VERSION 5.8 ;
BUSBITCHARS "[]" ;

UNITS
  DATABASE MICRONS 1000 ;
END UNITS

PROPERTYDEFINITIONS
  MACRO expanded_util REAL ;
END PROPERTYDEFINITIONS

LAYER OVERLAP
  TYPE OVERLAP ;
END OVERLAP

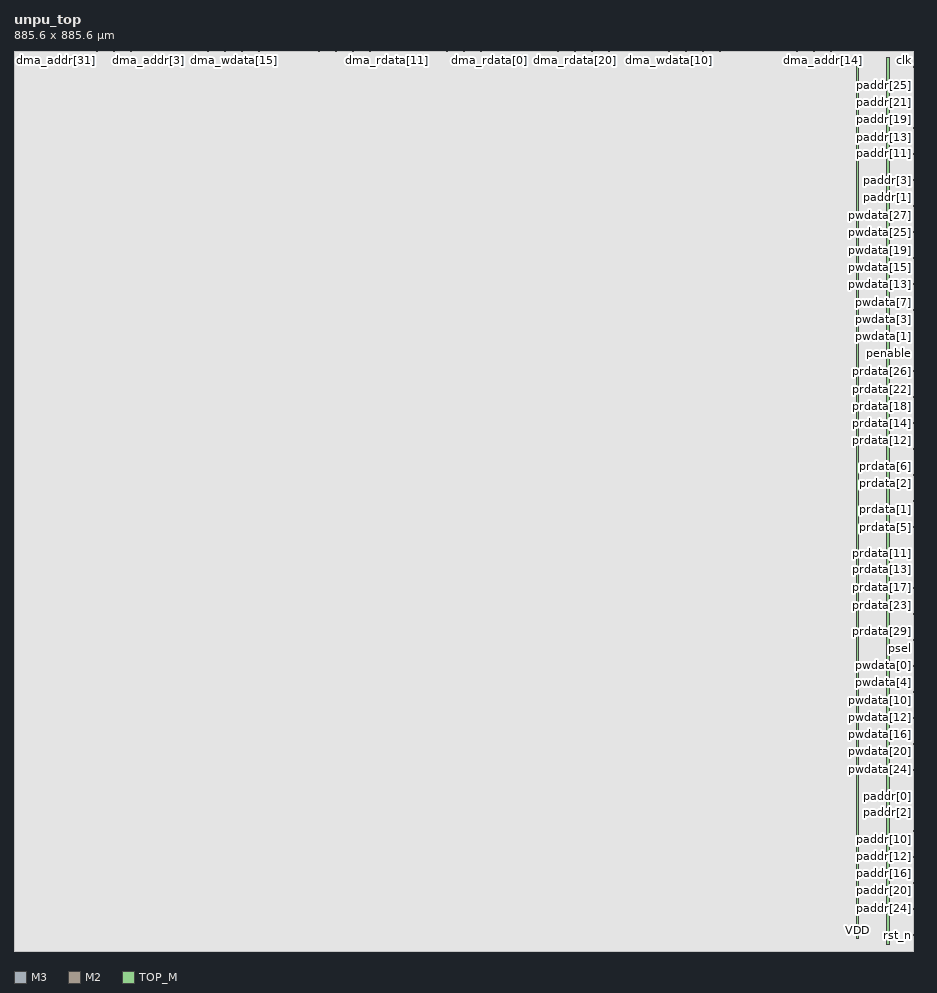
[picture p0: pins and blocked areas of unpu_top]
MACRO unpu_top
  CLASS BLOCK ;
  ORIGIN 0 0 ;
  SIZE 885.6 BY 885.6 ;
  SYMMETRY X Y ;
  PIN clk
    DIRECTION INPUT ;
    USE CLOCK ;
    PORT
      LAYER M3 ;
        RECT 884.875 878.13 885.6 878.41 ;
    END
  END clk
  PIN rst_n
    DIRECTION INPUT ;
    USE SIGNAL ;
    PORT
      LAYER M3 ;
        RECT 884.875 15.59 885.6 15.87 ;
    END
  END rst_n
  PIN paddr[31]
    DIRECTION INPUT ;
    USE SIGNAL ;
    PORT
      LAYER M3 ;
        RECT 884.875 869.59 885.6 869.87 ;
    END
  END paddr[31]
  PIN paddr[30]
    DIRECTION INPUT ;
    USE SIGNAL ;
    PORT
      LAYER M3 ;
        RECT 884.875 24.13 885.6 24.41 ;
    END
  END paddr[30]
  PIN paddr[29]
    DIRECTION INPUT ;
    USE SIGNAL ;
    PORT
      LAYER M3 ;
        RECT 884.875 861.05 885.6 861.33 ;
    END
  END paddr[29]
  PIN paddr[28]
    DIRECTION INPUT ;
    USE SIGNAL ;
    PORT
      LAYER M3 ;
        RECT 884.875 32.67 885.6 32.95 ;
    END
  END paddr[28]
  PIN paddr[27]
    DIRECTION INPUT ;
    USE SIGNAL ;
    PORT
      LAYER M3 ;
        RECT 884.875 852.51 885.6 852.79 ;
    END
  END paddr[27]
  PIN paddr[26]
    DIRECTION INPUT ;
    USE SIGNAL ;
    PORT
      LAYER M3 ;
        RECT 884.875 41.21 885.6 41.49 ;
    END
  END paddr[26]
  PIN paddr[25]
    DIRECTION INPUT ;
    USE SIGNAL ;
    PORT
      LAYER M3 ;
        RECT 884.875 843.97 885.6 844.25 ;
    END
  END paddr[25]
  PIN paddr[24]
    DIRECTION INPUT ;
    USE SIGNAL ;
    PORT
      LAYER M3 ;
        RECT 884.875 49.75 885.6 50.03 ;
    END
  END paddr[24]
  PIN paddr[23]
    DIRECTION INPUT ;
    USE SIGNAL ;
    PORT
      LAYER M3 ;
        RECT 884.875 835.43 885.6 835.71 ;
    END
  END paddr[23]
  PIN paddr[22]
    DIRECTION INPUT ;
    USE SIGNAL ;
    PORT
      LAYER M3 ;
        RECT 884.875 58.29 885.6 58.57 ;
    END
  END paddr[22]
  PIN paddr[21]
    DIRECTION INPUT ;
    USE SIGNAL ;
    PORT
      LAYER M3 ;
        RECT 884.875 826.89 885.6 827.17 ;
    END
  END paddr[21]
  PIN paddr[20]
    DIRECTION INPUT ;
    USE SIGNAL ;
    PORT
      LAYER M3 ;
        RECT 884.875 66.83 885.6 67.11 ;
    END
  END paddr[20]
  PIN paddr[19]
    DIRECTION INPUT ;
    USE SIGNAL ;
    PORT
      LAYER M3 ;
        RECT 884.875 818.35 885.6 818.63 ;
    END
  END paddr[19]
  PIN paddr[18]
    DIRECTION INPUT ;
    USE SIGNAL ;
    PORT
      LAYER M3 ;
        RECT 884.875 75.37 885.6 75.65 ;
    END
  END paddr[18]
  PIN paddr[17]
    DIRECTION INPUT ;
    USE SIGNAL ;
    PORT
      LAYER M3 ;
        RECT 884.875 809.81 885.6 810.09 ;
    END
  END paddr[17]
  PIN paddr[16]
    DIRECTION INPUT ;
    USE SIGNAL ;
    PORT
      LAYER M3 ;
        RECT 884.875 83.91 885.6 84.19 ;
    END
  END paddr[16]
  PIN paddr[15]
    DIRECTION INPUT ;
    USE SIGNAL ;
    PORT
      LAYER M3 ;
        RECT 884.875 801.27 885.6 801.55 ;
    END
  END paddr[15]
  PIN paddr[14]
    DIRECTION INPUT ;
    USE SIGNAL ;
    PORT
      LAYER M3 ;
        RECT 884.875 92.45 885.6 92.73 ;
    END
  END paddr[14]
  PIN paddr[13]
    DIRECTION INPUT ;
    USE SIGNAL ;
    PORT
      LAYER M3 ;
        RECT 884.875 792.73 885.6 793.01 ;
    END
  END paddr[13]
  PIN paddr[12]
    DIRECTION INPUT ;
    USE SIGNAL ;
    PORT
      LAYER M3 ;
        RECT 884.875 100.99 885.6 101.27 ;
    END
  END paddr[12]
  PIN paddr[11]
    DIRECTION INPUT ;
    USE SIGNAL ;
    PORT
      LAYER M3 ;
        RECT 884.875 784.19 885.6 784.47 ;
    END
  END paddr[11]
  PIN paddr[10]
    DIRECTION INPUT ;
    USE SIGNAL ;
    PORT
      LAYER M3 ;
        RECT 884.875 109.53 885.6 109.81 ;
    END
  END paddr[10]
  PIN paddr[9]
    DIRECTION INPUT ;
    USE SIGNAL ;
    PORT
      LAYER M3 ;
        RECT 884.875 775.65 885.6 775.93 ;
    END
  END paddr[9]
  PIN paddr[8]
    DIRECTION INPUT ;
    USE SIGNAL ;
    PORT
      LAYER M3 ;
        RECT 884.875 118.07 885.6 118.35 ;
    END
  END paddr[8]
  PIN paddr[7]
    DIRECTION INPUT ;
    USE SIGNAL ;
    PORT
      LAYER M3 ;
        RECT 884.875 767.11 885.6 767.39 ;
    END
  END paddr[7]
  PIN paddr[6]
    DIRECTION INPUT ;
    USE SIGNAL ;
    PORT
      LAYER M3 ;
        RECT 884.875 126.61 885.6 126.89 ;
    END
  END paddr[6]
  PIN paddr[5]
    DIRECTION INPUT ;
    USE SIGNAL ;
    PORT
      LAYER M3 ;
        RECT 884.875 758.57 885.6 758.85 ;
    END
  END paddr[5]
  PIN paddr[4]
    DIRECTION INPUT ;
    USE SIGNAL ;
    PORT
      LAYER M3 ;
        RECT 884.875 135.15 885.6 135.43 ;
    END
  END paddr[4]
  PIN paddr[3]
    DIRECTION INPUT ;
    USE SIGNAL ;
    PORT
      LAYER M3 ;
        RECT 884.875 750.03 885.6 750.31 ;
    END
  END paddr[3]
  PIN paddr[2]
    DIRECTION INPUT ;
    USE SIGNAL ;
    PORT
      LAYER M3 ;
        RECT 884.875 143.69 885.6 143.97 ;
    END
  END paddr[2]
  PIN paddr[1]
    DIRECTION INPUT ;
    USE SIGNAL ;
    PORT
      LAYER M3 ;
        RECT 884.875 741.49 885.6 741.77 ;
    END
  END paddr[1]
  PIN paddr[0]
    DIRECTION INPUT ;
    USE SIGNAL ;
    PORT
      LAYER M3 ;
        RECT 884.875 152.23 885.6 152.51 ;
    END
  END paddr[0]
  PIN pwdata[31]
    DIRECTION INPUT ;
    USE SIGNAL ;
    PORT
      LAYER M3 ;
        RECT 884.875 732.95 885.6 733.23 ;
    END
  END pwdata[31]
  PIN pwdata[30]
    DIRECTION INPUT ;
    USE SIGNAL ;
    PORT
      LAYER M3 ;
        RECT 884.875 160.77 885.6 161.05 ;
    END
  END pwdata[30]
  PIN pwdata[29]
    DIRECTION INPUT ;
    USE SIGNAL ;
    PORT
      LAYER M3 ;
        RECT 884.875 724.41 885.6 724.69 ;
    END
  END pwdata[29]
  PIN pwdata[28]
    DIRECTION INPUT ;
    USE SIGNAL ;
    PORT
      LAYER M3 ;
        RECT 884.875 169.31 885.6 169.59 ;
    END
  END pwdata[28]
  PIN pwdata[27]
    DIRECTION INPUT ;
    USE SIGNAL ;
    PORT
      LAYER M3 ;
        RECT 884.875 715.87 885.6 716.15 ;
    END
  END pwdata[27]
  PIN pwdata[26]
    DIRECTION INPUT ;
    USE SIGNAL ;
    PORT
      LAYER M3 ;
        RECT 884.875 177.85 885.6 178.13 ;
    END
  END pwdata[26]
  PIN pwdata[25]
    DIRECTION INPUT ;
    USE SIGNAL ;
    PORT
      LAYER M3 ;
        RECT 884.875 707.33 885.6 707.61 ;
    END
  END pwdata[25]
  PIN pwdata[24]
    DIRECTION INPUT ;
    USE SIGNAL ;
    PORT
      LAYER M3 ;
        RECT 884.875 186.39 885.6 186.67 ;
    END
  END pwdata[24]
  PIN pwdata[23]
    DIRECTION INPUT ;
    USE SIGNAL ;
    PORT
      LAYER M3 ;
        RECT 884.875 698.79 885.6 699.07 ;
    END
  END pwdata[23]
  PIN pwdata[22]
    DIRECTION INPUT ;
    USE SIGNAL ;
    PORT
      LAYER M3 ;
        RECT 884.875 194.93 885.6 195.21 ;
    END
  END pwdata[22]
  PIN pwdata[21]
    DIRECTION INPUT ;
    USE SIGNAL ;
    PORT
      LAYER M3 ;
        RECT 884.875 690.25 885.6 690.53 ;
    END
  END pwdata[21]
  PIN pwdata[20]
    DIRECTION INPUT ;
    USE SIGNAL ;
    PORT
      LAYER M3 ;
        RECT 884.875 203.47 885.6 203.75 ;
    END
  END pwdata[20]
  PIN pwdata[19]
    DIRECTION INPUT ;
    USE SIGNAL ;
    PORT
      LAYER M3 ;
        RECT 884.875 681.71 885.6 681.99 ;
    END
  END pwdata[19]
  PIN pwdata[18]
    DIRECTION INPUT ;
    USE SIGNAL ;
    PORT
      LAYER M3 ;
        RECT 884.875 212.01 885.6 212.29 ;
    END
  END pwdata[18]
  PIN pwdata[17]
    DIRECTION INPUT ;
    USE SIGNAL ;
    PORT
      LAYER M3 ;
        RECT 884.875 673.17 885.6 673.45 ;
    END
  END pwdata[17]
  PIN pwdata[16]
    DIRECTION INPUT ;
    USE SIGNAL ;
    PORT
      LAYER M3 ;
        RECT 884.875 220.55 885.6 220.83 ;
    END
  END pwdata[16]
  PIN pwdata[15]
    DIRECTION INPUT ;
    USE SIGNAL ;
    PORT
      LAYER M3 ;
        RECT 884.875 664.63 885.6 664.91 ;
    END
  END pwdata[15]
  PIN pwdata[14]
    DIRECTION INPUT ;
    USE SIGNAL ;
    PORT
      LAYER M3 ;
        RECT 884.875 229.09 885.6 229.37 ;
    END
  END pwdata[14]
  PIN pwdata[13]
    DIRECTION INPUT ;
    USE SIGNAL ;
    PORT
      LAYER M3 ;
        RECT 884.875 656.09 885.6 656.37 ;
    END
  END pwdata[13]
  PIN pwdata[12]
    DIRECTION INPUT ;
    USE SIGNAL ;
    PORT
      LAYER M3 ;
        RECT 884.875 237.63 885.6 237.91 ;
    END
  END pwdata[12]
  PIN pwdata[11]
    DIRECTION INPUT ;
    USE SIGNAL ;
    PORT
      LAYER M3 ;
        RECT 884.875 647.55 885.6 647.83 ;
    END
  END pwdata[11]
  PIN pwdata[10]
    DIRECTION INPUT ;
    USE SIGNAL ;
    PORT
      LAYER M3 ;
        RECT 884.875 246.17 885.6 246.45 ;
    END
  END pwdata[10]
  PIN pwdata[9]
    DIRECTION INPUT ;
    USE SIGNAL ;
    PORT
      LAYER M3 ;
        RECT 884.875 639.01 885.6 639.29 ;
    END
  END pwdata[9]
  PIN pwdata[8]
    DIRECTION INPUT ;
    USE SIGNAL ;
    PORT
      LAYER M3 ;
        RECT 884.875 254.71 885.6 254.99 ;
    END
  END pwdata[8]
  PIN pwdata[7]
    DIRECTION INPUT ;
    USE SIGNAL ;
    PORT
      LAYER M3 ;
        RECT 884.875 630.47 885.6 630.75 ;
    END
  END pwdata[7]
  PIN pwdata[6]
    DIRECTION INPUT ;
    USE SIGNAL ;
    PORT
      LAYER M3 ;
        RECT 884.875 263.25 885.6 263.53 ;
    END
  END pwdata[6]
  PIN pwdata[5]
    DIRECTION INPUT ;
    USE SIGNAL ;
    PORT
      LAYER M3 ;
        RECT 884.875 621.93 885.6 622.21 ;
    END
  END pwdata[5]
  PIN pwdata[4]
    DIRECTION INPUT ;
    USE SIGNAL ;
    PORT
      LAYER M3 ;
        RECT 884.875 271.79 885.6 272.07 ;
    END
  END pwdata[4]
  PIN pwdata[3]
    DIRECTION INPUT ;
    USE SIGNAL ;
    PORT
      LAYER M3 ;
        RECT 884.875 613.39 885.6 613.67 ;
    END
  END pwdata[3]
  PIN pwdata[2]
    DIRECTION INPUT ;
    USE SIGNAL ;
    PORT
      LAYER M3 ;
        RECT 884.875 280.33 885.6 280.61 ;
    END
  END pwdata[2]
  PIN pwdata[1]
    DIRECTION INPUT ;
    USE SIGNAL ;
    PORT
      LAYER M3 ;
        RECT 884.875 604.85 885.6 605.13 ;
    END
  END pwdata[1]
  PIN pwdata[0]
    DIRECTION INPUT ;
    USE SIGNAL ;
    PORT
      LAYER M3 ;
        RECT 884.875 288.87 885.6 289.15 ;
    END
  END pwdata[0]
  PIN pwrite
    DIRECTION INPUT ;
    USE SIGNAL ;
    PORT
      LAYER M3 ;
        RECT 884.875 596.31 885.6 596.59 ;
    END
  END pwrite
  PIN psel
    DIRECTION INPUT ;
    USE SIGNAL ;
    PORT
      LAYER M3 ;
        RECT 884.875 297.41 885.6 297.69 ;
    END
  END psel
  PIN penable
    DIRECTION INPUT ;
    USE SIGNAL ;
    PORT
      LAYER M3 ;
        RECT 884.875 587.77 885.6 588.05 ;
    END
  END penable
  PIN prdata[31]
    DIRECTION OUTPUT ;
    USE SIGNAL ;
    PORT
      LAYER M3 ;
        RECT 884.875 305.95 885.6 306.23 ;
    END
  END prdata[31]
  PIN prdata[30]
    DIRECTION OUTPUT ;
    USE SIGNAL ;
    PORT
      LAYER M3 ;
        RECT 884.875 579.23 885.6 579.51 ;
    END
  END prdata[30]
  PIN prdata[29]
    DIRECTION OUTPUT ;
    USE SIGNAL ;
    PORT
      LAYER M3 ;
        RECT 884.875 314.49 885.6 314.77 ;
    END
  END prdata[29]
  PIN prdata[28]
    DIRECTION OUTPUT ;
    USE SIGNAL ;
    PORT
      LAYER M3 ;
        RECT 884.875 570.69 885.6 570.97 ;
    END
  END prdata[28]
  PIN prdata[27]
    DIRECTION OUTPUT ;
    USE SIGNAL ;
    PORT
      LAYER M3 ;
        RECT 884.875 323.03 885.6 323.31 ;
    END
  END prdata[27]
  PIN prdata[26]
    DIRECTION OUTPUT ;
    USE SIGNAL ;
    PORT
      LAYER M3 ;
        RECT 884.875 562.15 885.6 562.43 ;
    END
  END prdata[26]
  PIN prdata[25]
    DIRECTION OUTPUT ;
    USE SIGNAL ;
    PORT
      LAYER M3 ;
        RECT 884.875 331.57 885.6 331.85 ;
    END
  END prdata[25]
  PIN prdata[24]
    DIRECTION OUTPUT ;
    USE SIGNAL ;
    PORT
      LAYER M3 ;
        RECT 884.875 553.61 885.6 553.89 ;
    END
  END prdata[24]
  PIN prdata[23]
    DIRECTION OUTPUT ;
    USE SIGNAL ;
    PORT
      LAYER M3 ;
        RECT 884.875 340.11 885.6 340.39 ;
    END
  END prdata[23]
  PIN prdata[22]
    DIRECTION OUTPUT ;
    USE SIGNAL ;
    PORT
      LAYER M3 ;
        RECT 884.875 545.07 885.6 545.35 ;
    END
  END prdata[22]
  PIN prdata[21]
    DIRECTION OUTPUT ;
    USE SIGNAL ;
    PORT
      LAYER M3 ;
        RECT 884.875 348.65 885.6 348.93 ;
    END
  END prdata[21]
  PIN prdata[20]
    DIRECTION OUTPUT ;
    USE SIGNAL ;
    PORT
      LAYER M3 ;
        RECT 884.875 536.53 885.6 536.81 ;
    END
  END prdata[20]
  PIN prdata[19]
    DIRECTION OUTPUT ;
    USE SIGNAL ;
    PORT
      LAYER M3 ;
        RECT 884.875 357.19 885.6 357.47 ;
    END
  END prdata[19]
  PIN prdata[18]
    DIRECTION OUTPUT ;
    USE SIGNAL ;
    PORT
      LAYER M3 ;
        RECT 884.875 527.99 885.6 528.27 ;
    END
  END prdata[18]
  PIN prdata[17]
    DIRECTION OUTPUT ;
    USE SIGNAL ;
    PORT
      LAYER M3 ;
        RECT 884.875 365.73 885.6 366.01 ;
    END
  END prdata[17]
  PIN prdata[16]
    DIRECTION OUTPUT ;
    USE SIGNAL ;
    PORT
      LAYER M3 ;
        RECT 884.875 519.45 885.6 519.73 ;
    END
  END prdata[16]
  PIN prdata[15]
    DIRECTION OUTPUT ;
    USE SIGNAL ;
    PORT
      LAYER M3 ;
        RECT 884.875 374.27 885.6 374.55 ;
    END
  END prdata[15]
  PIN prdata[14]
    DIRECTION OUTPUT ;
    USE SIGNAL ;
    PORT
      LAYER M3 ;
        RECT 884.875 510.91 885.6 511.19 ;
    END
  END prdata[14]
  PIN prdata[13]
    DIRECTION OUTPUT ;
    USE SIGNAL ;
    PORT
      LAYER M3 ;
        RECT 884.875 382.81 885.6 383.09 ;
    END
  END prdata[13]
  PIN prdata[12]
    DIRECTION OUTPUT ;
    USE SIGNAL ;
    PORT
      LAYER M3 ;
        RECT 884.875 502.37 885.6 502.65 ;
    END
  END prdata[12]
  PIN prdata[11]
    DIRECTION OUTPUT ;
    USE SIGNAL ;
    PORT
      LAYER M3 ;
        RECT 884.875 391.35 885.6 391.63 ;
    END
  END prdata[11]
  PIN prdata[10]
    DIRECTION OUTPUT ;
    USE SIGNAL ;
    PORT
      LAYER M3 ;
        RECT 884.875 493.83 885.6 494.11 ;
    END
  END prdata[10]
  PIN prdata[9]
    DIRECTION OUTPUT ;
    USE SIGNAL ;
    PORT
      LAYER M3 ;
        RECT 884.875 399.89 885.6 400.17 ;
    END
  END prdata[9]
  PIN prdata[8]
    DIRECTION OUTPUT ;
    USE SIGNAL ;
    PORT
      LAYER M3 ;
        RECT 884.875 485.29 885.6 485.57 ;
    END
  END prdata[8]
  PIN prdata[7]
    DIRECTION OUTPUT ;
    USE SIGNAL ;
    PORT
      LAYER M3 ;
        RECT 884.875 408.43 885.6 408.71 ;
    END
  END prdata[7]
  PIN prdata[6]
    DIRECTION OUTPUT ;
    USE SIGNAL ;
    PORT
      LAYER M3 ;
        RECT 884.875 476.75 885.6 477.03 ;
    END
  END prdata[6]
  PIN prdata[5]
    DIRECTION OUTPUT ;
    USE SIGNAL ;
    PORT
      LAYER M3 ;
        RECT 884.875 416.97 885.6 417.25 ;
    END
  END prdata[5]
  PIN prdata[4]
    DIRECTION OUTPUT ;
    USE SIGNAL ;
    PORT
      LAYER M3 ;
        RECT 884.875 468.21 885.6 468.49 ;
    END
  END prdata[4]
  PIN prdata[3]
    DIRECTION OUTPUT ;
    USE SIGNAL ;
    PORT
      LAYER M3 ;
        RECT 884.875 425.51 885.6 425.79 ;
    END
  END prdata[3]
  PIN prdata[2]
    DIRECTION OUTPUT ;
    USE SIGNAL ;
    PORT
      LAYER M3 ;
        RECT 884.875 459.67 885.6 459.95 ;
    END
  END prdata[2]
  PIN prdata[1]
    DIRECTION OUTPUT ;
    USE SIGNAL ;
    PORT
      LAYER M3 ;
        RECT 884.875 434.05 885.6 434.33 ;
    END
  END prdata[1]
  PIN prdata[0]
    DIRECTION OUTPUT ;
    USE SIGNAL ;
    PORT
      LAYER M3 ;
        RECT 884.875 451.13 885.6 451.41 ;
    END
  END prdata[0]
  PIN pready
    DIRECTION OUTPUT ;
    USE SIGNAL ;
    PORT
      LAYER M3 ;
        RECT 884.875 442.59 885.6 442.87 ;
    END
  END pready
  PIN dma_addr[31]
    DIRECTION OUTPUT ;
    USE SIGNAL ;
    PORT
      LAYER M2 ;
        RECT 14.26 884.875 14.54 885.6 ;
    END
  END dma_addr[31]
  PIN dma_addr[30]
    DIRECTION OUTPUT ;
    USE SIGNAL ;
    PORT
      LAYER M2 ;
        RECT 862.66 884.875 862.94 885.6 ;
    END
  END dma_addr[30]
  PIN dma_addr[29]
    DIRECTION OUTPUT ;
    USE SIGNAL ;
    PORT
      LAYER M2 ;
        RECT 22.66 884.875 22.94 885.6 ;
    END
  END dma_addr[29]
  PIN dma_addr[28]
    DIRECTION OUTPUT ;
    USE SIGNAL ;
    PORT
      LAYER M2 ;
        RECT 854.26 884.875 854.54 885.6 ;
    END
  END dma_addr[28]
  PIN dma_addr[27]
    DIRECTION OUTPUT ;
    USE SIGNAL ;
    PORT
      LAYER M2 ;
        RECT 31.06 884.875 31.34 885.6 ;
    END
  END dma_addr[27]
  PIN dma_addr[26]
    DIRECTION OUTPUT ;
    USE SIGNAL ;
    PORT
      LAYER M2 ;
        RECT 845.86 884.875 846.14 885.6 ;
    END
  END dma_addr[26]
  PIN dma_addr[25]
    DIRECTION OUTPUT ;
    USE SIGNAL ;
    PORT
      LAYER M2 ;
        RECT 39.46 884.875 39.74 885.6 ;
    END
  END dma_addr[25]
  PIN dma_addr[24]
    DIRECTION OUTPUT ;
    USE SIGNAL ;
    PORT
      LAYER M2 ;
        RECT 837.46 884.875 837.74 885.6 ;
    END
  END dma_addr[24]
  PIN dma_addr[23]
    DIRECTION OUTPUT ;
    USE SIGNAL ;
    PORT
      LAYER M2 ;
        RECT 47.86 884.875 48.14 885.6 ;
    END
  END dma_addr[23]
  PIN dma_addr[22]
    DIRECTION OUTPUT ;
    USE SIGNAL ;
    PORT
      LAYER M2 ;
        RECT 829.06 884.875 829.34 885.6 ;
    END
  END dma_addr[22]
  PIN dma_addr[21]
    DIRECTION OUTPUT ;
    USE SIGNAL ;
    PORT
      LAYER M2 ;
        RECT 56.26 884.875 56.54 885.6 ;
    END
  END dma_addr[21]
  PIN dma_addr[20]
    DIRECTION OUTPUT ;
    USE SIGNAL ;
    PORT
      LAYER M2 ;
        RECT 820.66 884.875 820.94 885.6 ;
    END
  END dma_addr[20]
  PIN dma_addr[19]
    DIRECTION OUTPUT ;
    USE SIGNAL ;
    PORT
      LAYER M2 ;
        RECT 64.66 884.875 64.94 885.6 ;
    END
  END dma_addr[19]
  PIN dma_addr[18]
    DIRECTION OUTPUT ;
    USE SIGNAL ;
    PORT
      LAYER M2 ;
        RECT 812.26 884.875 812.54 885.6 ;
    END
  END dma_addr[18]
  PIN dma_addr[17]
    DIRECTION OUTPUT ;
    USE SIGNAL ;
    PORT
      LAYER M2 ;
        RECT 73.06 884.875 73.34 885.6 ;
    END
  END dma_addr[17]
  PIN dma_addr[16]
    DIRECTION OUTPUT ;
    USE SIGNAL ;
    PORT
      LAYER M2 ;
        RECT 803.86 884.875 804.14 885.6 ;
    END
  END dma_addr[16]
  PIN dma_addr[15]
    DIRECTION OUTPUT ;
    USE SIGNAL ;
    PORT
      LAYER M2 ;
        RECT 81.46 884.875 81.74 885.6 ;
    END
  END dma_addr[15]
  PIN dma_addr[14]
    DIRECTION OUTPUT ;
    USE SIGNAL ;
    PORT
      LAYER M2 ;
        RECT 795.46 884.875 795.74 885.6 ;
    END
  END dma_addr[14]
  PIN dma_addr[13]
    DIRECTION OUTPUT ;
    USE SIGNAL ;
    PORT
      LAYER M2 ;
        RECT 89.86 884.875 90.14 885.6 ;
    END
  END dma_addr[13]
  PIN dma_addr[12]
    DIRECTION OUTPUT ;
    USE SIGNAL ;
    PORT
      LAYER M2 ;
        RECT 787.06 884.875 787.34 885.6 ;
    END
  END dma_addr[12]
  PIN dma_addr[11]
    DIRECTION OUTPUT ;
    USE SIGNAL ;
    PORT
      LAYER M2 ;
        RECT 98.26 884.875 98.54 885.6 ;
    END
  END dma_addr[11]
  PIN dma_addr[10]
    DIRECTION OUTPUT ;
    USE SIGNAL ;
    PORT
      LAYER M2 ;
        RECT 778.66 884.875 778.94 885.6 ;
    END
  END dma_addr[10]
  PIN dma_addr[9]
    DIRECTION OUTPUT ;
    USE SIGNAL ;
    PORT
      LAYER M2 ;
        RECT 106.66 884.875 106.94 885.6 ;
    END
  END dma_addr[9]
  PIN dma_addr[8]
    DIRECTION OUTPUT ;
    USE SIGNAL ;
    PORT
      LAYER M2 ;
        RECT 770.26 884.875 770.54 885.6 ;
    END
  END dma_addr[8]
  PIN dma_addr[7]
    DIRECTION OUTPUT ;
    USE SIGNAL ;
    PORT
      LAYER M2 ;
        RECT 115.06 884.875 115.34 885.6 ;
    END
  END dma_addr[7]
  PIN dma_addr[6]
    DIRECTION OUTPUT ;
    USE SIGNAL ;
    PORT
      LAYER M2 ;
        RECT 761.86 884.875 762.14 885.6 ;
    END
  END dma_addr[6]
  PIN dma_addr[5]
    DIRECTION OUTPUT ;
    USE SIGNAL ;
    PORT
      LAYER M2 ;
        RECT 123.46 884.875 123.74 885.6 ;
    END
  END dma_addr[5]
  PIN dma_addr[4]
    DIRECTION OUTPUT ;
    USE SIGNAL ;
    PORT
      LAYER M2 ;
        RECT 753.46 884.875 753.74 885.6 ;
    END
  END dma_addr[4]
  PIN dma_addr[3]
    DIRECTION OUTPUT ;
    USE SIGNAL ;
    PORT
      LAYER M2 ;
        RECT 131.86 884.875 132.14 885.6 ;
    END
  END dma_addr[3]
  PIN dma_addr[2]
    DIRECTION OUTPUT ;
    USE SIGNAL ;
    PORT
      LAYER M2 ;
        RECT 745.06 884.875 745.34 885.6 ;
    END
  END dma_addr[2]
  PIN dma_addr[1]
    DIRECTION OUTPUT ;
    USE SIGNAL ;
    PORT
      LAYER M2 ;
        RECT 140.26 884.875 140.54 885.6 ;
    END
  END dma_addr[1]
  PIN dma_addr[0]
    DIRECTION OUTPUT ;
    USE SIGNAL ;
    PORT
      LAYER M2 ;
        RECT 736.66 884.875 736.94 885.6 ;
    END
  END dma_addr[0]
  PIN dma_wdata[31]
    DIRECTION OUTPUT ;
    USE SIGNAL ;
    PORT
      LAYER M2 ;
        RECT 148.66 884.875 148.94 885.6 ;
    END
  END dma_wdata[31]
  PIN dma_wdata[30]
    DIRECTION OUTPUT ;
    USE SIGNAL ;
    PORT
      LAYER M2 ;
        RECT 728.26 884.875 728.54 885.6 ;
    END
  END dma_wdata[30]
  PIN dma_wdata[29]
    DIRECTION OUTPUT ;
    USE SIGNAL ;
    PORT
      LAYER M2 ;
        RECT 157.06 884.875 157.34 885.6 ;
    END
  END dma_wdata[29]
  PIN dma_wdata[28]
    DIRECTION OUTPUT ;
    USE SIGNAL ;
    PORT
      LAYER M2 ;
        RECT 719.86 884.875 720.14 885.6 ;
    END
  END dma_wdata[28]
  PIN dma_wdata[27]
    DIRECTION OUTPUT ;
    USE SIGNAL ;
    PORT
      LAYER M2 ;
        RECT 165.46 884.875 165.74 885.6 ;
    END
  END dma_wdata[27]
  PIN dma_wdata[26]
    DIRECTION OUTPUT ;
    USE SIGNAL ;
    PORT
      LAYER M2 ;
        RECT 711.46 884.875 711.74 885.6 ;
    END
  END dma_wdata[26]
  PIN dma_wdata[25]
    DIRECTION OUTPUT ;
    USE SIGNAL ;
    PORT
      LAYER M2 ;
        RECT 173.86 884.875 174.14 885.6 ;
    END
  END dma_wdata[25]
  PIN dma_wdata[24]
    DIRECTION OUTPUT ;
    USE SIGNAL ;
    PORT
      LAYER M2 ;
        RECT 703.06 884.875 703.34 885.6 ;
    END
  END dma_wdata[24]
  PIN dma_wdata[23]
    DIRECTION OUTPUT ;
    USE SIGNAL ;
    PORT
      LAYER M2 ;
        RECT 182.26 884.875 182.54 885.6 ;
    END
  END dma_wdata[23]
  PIN dma_wdata[22]
    DIRECTION OUTPUT ;
    USE SIGNAL ;
    PORT
      LAYER M2 ;
        RECT 694.66 884.875 694.94 885.6 ;
    END
  END dma_wdata[22]
  PIN dma_wdata[21]
    DIRECTION OUTPUT ;
    USE SIGNAL ;
    PORT
      LAYER M2 ;
        RECT 190.66 884.875 190.94 885.6 ;
    END
  END dma_wdata[21]
  PIN dma_wdata[20]
    DIRECTION OUTPUT ;
    USE SIGNAL ;
    PORT
      LAYER M2 ;
        RECT 686.26 884.875 686.54 885.6 ;
    END
  END dma_wdata[20]
  PIN dma_wdata[19]
    DIRECTION OUTPUT ;
    USE SIGNAL ;
    PORT
      LAYER M2 ;
        RECT 199.06 884.875 199.34 885.6 ;
    END
  END dma_wdata[19]
  PIN dma_wdata[18]
    DIRECTION OUTPUT ;
    USE SIGNAL ;
    PORT
      LAYER M2 ;
        RECT 677.86 884.875 678.14 885.6 ;
    END
  END dma_wdata[18]
  PIN dma_wdata[17]
    DIRECTION OUTPUT ;
    USE SIGNAL ;
    PORT
      LAYER M2 ;
        RECT 207.46 884.875 207.74 885.6 ;
    END
  END dma_wdata[17]
  PIN dma_wdata[16]
    DIRECTION OUTPUT ;
    USE SIGNAL ;
    PORT
      LAYER M2 ;
        RECT 669.46 884.875 669.74 885.6 ;
    END
  END dma_wdata[16]
  PIN dma_wdata[15]
    DIRECTION OUTPUT ;
    USE SIGNAL ;
    PORT
      LAYER M2 ;
        RECT 215.86 884.875 216.14 885.6 ;
    END
  END dma_wdata[15]
  PIN dma_wdata[14]
    DIRECTION OUTPUT ;
    USE SIGNAL ;
    PORT
      LAYER M2 ;
        RECT 661.06 884.875 661.34 885.6 ;
    END
  END dma_wdata[14]
  PIN dma_wdata[13]
    DIRECTION OUTPUT ;
    USE SIGNAL ;
    PORT
      LAYER M2 ;
        RECT 224.26 884.875 224.54 885.6 ;
    END
  END dma_wdata[13]
  PIN dma_wdata[12]
    DIRECTION OUTPUT ;
    USE SIGNAL ;
    PORT
      LAYER M2 ;
        RECT 652.66 884.875 652.94 885.6 ;
    END
  END dma_wdata[12]
  PIN dma_wdata[11]
    DIRECTION OUTPUT ;
    USE SIGNAL ;
    PORT
      LAYER M2 ;
        RECT 232.66 884.875 232.94 885.6 ;
    END
  END dma_wdata[11]
  PIN dma_wdata[10]
    DIRECTION OUTPUT ;
    USE SIGNAL ;
    PORT
      LAYER M2 ;
        RECT 644.26 884.875 644.54 885.6 ;
    END
  END dma_wdata[10]
  PIN dma_wdata[9]
    DIRECTION OUTPUT ;
    USE SIGNAL ;
    PORT
      LAYER M2 ;
        RECT 241.06 884.875 241.34 885.6 ;
    END
  END dma_wdata[9]
  PIN dma_wdata[8]
    DIRECTION OUTPUT ;
    USE SIGNAL ;
    PORT
      LAYER M2 ;
        RECT 635.86 884.875 636.14 885.6 ;
    END
  END dma_wdata[8]
  PIN dma_wdata[7]
    DIRECTION OUTPUT ;
    USE SIGNAL ;
    PORT
      LAYER M2 ;
        RECT 249.46 884.875 249.74 885.6 ;
    END
  END dma_wdata[7]
  PIN dma_wdata[6]
    DIRECTION OUTPUT ;
    USE SIGNAL ;
    PORT
      LAYER M2 ;
        RECT 627.46 884.875 627.74 885.6 ;
    END
  END dma_wdata[6]
  PIN dma_wdata[5]
    DIRECTION OUTPUT ;
    USE SIGNAL ;
    PORT
      LAYER M2 ;
        RECT 257.86 884.875 258.14 885.6 ;
    END
  END dma_wdata[5]
  PIN dma_wdata[4]
    DIRECTION OUTPUT ;
    USE SIGNAL ;
    PORT
      LAYER M2 ;
        RECT 619.06 884.875 619.34 885.6 ;
    END
  END dma_wdata[4]
  PIN dma_wdata[3]
    DIRECTION OUTPUT ;
    USE SIGNAL ;
    PORT
      LAYER M2 ;
        RECT 266.26 884.875 266.54 885.6 ;
    END
  END dma_wdata[3]
  PIN dma_wdata[2]
    DIRECTION OUTPUT ;
    USE SIGNAL ;
    PORT
      LAYER M2 ;
        RECT 610.66 884.875 610.94 885.6 ;
    END
  END dma_wdata[2]
  PIN dma_wdata[1]
    DIRECTION OUTPUT ;
    USE SIGNAL ;
    PORT
      LAYER M2 ;
        RECT 274.66 884.875 274.94 885.6 ;
    END
  END dma_wdata[1]
  PIN dma_wdata[0]
    DIRECTION OUTPUT ;
    USE SIGNAL ;
    PORT
      LAYER M2 ;
        RECT 602.26 884.875 602.54 885.6 ;
    END
  END dma_wdata[0]
  PIN dma_rdata[31]
    DIRECTION INPUT ;
    USE SIGNAL ;
    PORT
      LAYER M2 ;
        RECT 283.06 884.875 283.34 885.6 ;
    END
  END dma_rdata[31]
  PIN dma_rdata[30]
    DIRECTION INPUT ;
    USE SIGNAL ;
    PORT
      LAYER M2 ;
        RECT 593.86 884.875 594.14 885.6 ;
    END
  END dma_rdata[30]
  PIN dma_rdata[29]
    DIRECTION INPUT ;
    USE SIGNAL ;
    PORT
      LAYER M2 ;
        RECT 291.46 884.875 291.74 885.6 ;
    END
  END dma_rdata[29]
  PIN dma_rdata[28]
    DIRECTION INPUT ;
    USE SIGNAL ;
    PORT
      LAYER M2 ;
        RECT 585.46 884.875 585.74 885.6 ;
    END
  END dma_rdata[28]
  PIN dma_rdata[27]
    DIRECTION INPUT ;
    USE SIGNAL ;
    PORT
      LAYER M2 ;
        RECT 299.86 884.875 300.14 885.6 ;
    END
  END dma_rdata[27]
  PIN dma_rdata[26]
    DIRECTION INPUT ;
    USE SIGNAL ;
    PORT
      LAYER M2 ;
        RECT 577.06 884.875 577.34 885.6 ;
    END
  END dma_rdata[26]
  PIN dma_rdata[25]
    DIRECTION INPUT ;
    USE SIGNAL ;
    PORT
      LAYER M2 ;
        RECT 308.26 884.875 308.54 885.6 ;
    END
  END dma_rdata[25]
  PIN dma_rdata[24]
    DIRECTION INPUT ;
    USE SIGNAL ;
    PORT
      LAYER M2 ;
        RECT 568.66 884.875 568.94 885.6 ;
    END
  END dma_rdata[24]
  PIN dma_rdata[23]
    DIRECTION INPUT ;
    USE SIGNAL ;
    PORT
      LAYER M2 ;
        RECT 316.66 884.875 316.94 885.6 ;
    END
  END dma_rdata[23]
  PIN dma_rdata[22]
    DIRECTION INPUT ;
    USE SIGNAL ;
    PORT
      LAYER M2 ;
        RECT 560.26 884.875 560.54 885.6 ;
    END
  END dma_rdata[22]
  PIN dma_rdata[21]
    DIRECTION INPUT ;
    USE SIGNAL ;
    PORT
      LAYER M2 ;
        RECT 325.06 884.875 325.34 885.6 ;
    END
  END dma_rdata[21]
  PIN dma_rdata[20]
    DIRECTION INPUT ;
    USE SIGNAL ;
    PORT
      LAYER M2 ;
        RECT 551.86 884.875 552.14 885.6 ;
    END
  END dma_rdata[20]
  PIN dma_rdata[19]
    DIRECTION INPUT ;
    USE SIGNAL ;
    PORT
      LAYER M2 ;
        RECT 333.46 884.875 333.74 885.6 ;
    END
  END dma_rdata[19]
  PIN dma_rdata[18]
    DIRECTION INPUT ;
    USE SIGNAL ;
    PORT
      LAYER M2 ;
        RECT 543.46 884.875 543.74 885.6 ;
    END
  END dma_rdata[18]
  PIN dma_rdata[17]
    DIRECTION INPUT ;
    USE SIGNAL ;
    PORT
      LAYER M2 ;
        RECT 341.86 884.875 342.14 885.6 ;
    END
  END dma_rdata[17]
  PIN dma_rdata[16]
    DIRECTION INPUT ;
    USE SIGNAL ;
    PORT
      LAYER M2 ;
        RECT 535.06 884.875 535.34 885.6 ;
    END
  END dma_rdata[16]
  PIN dma_rdata[15]
    DIRECTION INPUT ;
    USE SIGNAL ;
    PORT
      LAYER M2 ;
        RECT 350.26 884.875 350.54 885.6 ;
    END
  END dma_rdata[15]
  PIN dma_rdata[14]
    DIRECTION INPUT ;
    USE SIGNAL ;
    PORT
      LAYER M2 ;
        RECT 526.66 884.875 526.94 885.6 ;
    END
  END dma_rdata[14]
  PIN dma_rdata[13]
    DIRECTION INPUT ;
    USE SIGNAL ;
    PORT
      LAYER M2 ;
        RECT 358.66 884.875 358.94 885.6 ;
    END
  END dma_rdata[13]
  PIN dma_rdata[12]
    DIRECTION INPUT ;
    USE SIGNAL ;
    PORT
      LAYER M2 ;
        RECT 518.26 884.875 518.54 885.6 ;
    END
  END dma_rdata[12]
  PIN dma_rdata[11]
    DIRECTION INPUT ;
    USE SIGNAL ;
    PORT
      LAYER M2 ;
        RECT 367.06 884.875 367.34 885.6 ;
    END
  END dma_rdata[11]
  PIN dma_rdata[10]
    DIRECTION INPUT ;
    USE SIGNAL ;
    PORT
      LAYER M2 ;
        RECT 509.86 884.875 510.14 885.6 ;
    END
  END dma_rdata[10]
  PIN dma_rdata[9]
    DIRECTION INPUT ;
    USE SIGNAL ;
    PORT
      LAYER M2 ;
        RECT 375.46 884.875 375.74 885.6 ;
    END
  END dma_rdata[9]
  PIN dma_rdata[8]
    DIRECTION INPUT ;
    USE SIGNAL ;
    PORT
      LAYER M2 ;
        RECT 501.46 884.875 501.74 885.6 ;
    END
  END dma_rdata[8]
  PIN dma_rdata[7]
    DIRECTION INPUT ;
    USE SIGNAL ;
    PORT
      LAYER M2 ;
        RECT 383.86 884.875 384.14 885.6 ;
    END
  END dma_rdata[7]
  PIN dma_rdata[6]
    DIRECTION INPUT ;
    USE SIGNAL ;
    PORT
      LAYER M2 ;
        RECT 493.06 884.875 493.34 885.6 ;
    END
  END dma_rdata[6]
  PIN dma_rdata[5]
    DIRECTION INPUT ;
    USE SIGNAL ;
    PORT
      LAYER M2 ;
        RECT 392.26 884.875 392.54 885.6 ;
    END
  END dma_rdata[5]
  PIN dma_rdata[4]
    DIRECTION INPUT ;
    USE SIGNAL ;
    PORT
      LAYER M2 ;
        RECT 484.66 884.875 484.94 885.6 ;
    END
  END dma_rdata[4]
  PIN dma_rdata[3]
    DIRECTION INPUT ;
    USE SIGNAL ;
    PORT
      LAYER M2 ;
        RECT 400.66 884.875 400.94 885.6 ;
    END
  END dma_rdata[3]
  PIN dma_rdata[2]
    DIRECTION INPUT ;
    USE SIGNAL ;
    PORT
      LAYER M2 ;
        RECT 476.26 884.875 476.54 885.6 ;
    END
  END dma_rdata[2]
  PIN dma_rdata[1]
    DIRECTION INPUT ;
    USE SIGNAL ;
    PORT
      LAYER M2 ;
        RECT 409.06 884.875 409.34 885.6 ;
    END
  END dma_rdata[1]
  PIN dma_rdata[0]
    DIRECTION INPUT ;
    USE SIGNAL ;
    PORT
      LAYER M2 ;
        RECT 467.86 884.875 468.14 885.6 ;
    END
  END dma_rdata[0]
  PIN dma_wstrb[3]
    DIRECTION OUTPUT ;
    USE SIGNAL ;
    PORT
      LAYER M2 ;
        RECT 417.46 884.875 417.74 885.6 ;
    END
  END dma_wstrb[3]
  PIN dma_wstrb[2]
    DIRECTION OUTPUT ;
    USE SIGNAL ;
    PORT
      LAYER M2 ;
        RECT 459.46 884.875 459.74 885.6 ;
    END
  END dma_wstrb[2]
  PIN dma_wstrb[1]
    DIRECTION OUTPUT ;
    USE SIGNAL ;
    PORT
      LAYER M2 ;
        RECT 425.86 884.875 426.14 885.6 ;
    END
  END dma_wstrb[1]
  PIN dma_wstrb[0]
    DIRECTION OUTPUT ;
    USE SIGNAL ;
    PORT
      LAYER M2 ;
        RECT 451.06 884.875 451.34 885.6 ;
    END
  END dma_wstrb[0]
  PIN dma_valid
    DIRECTION OUTPUT ;
    USE SIGNAL ;
    PORT
      LAYER M2 ;
        RECT 434.26 884.875 434.54 885.6 ;
    END
  END dma_valid
  PIN dma_ready
    DIRECTION INPUT ;
    USE SIGNAL ;
    PORT
      LAYER M2 ;
        RECT 442.66 884.875 442.94 885.6 ;
    END
  END dma_ready
  PIN VDD
    DIRECTION INPUT ;
    USE POWER ;
    PORT
      LAYER TOP_M ;
        RECT 828.75 12 831.25 873.6 ;
    END
  END VDD
  PIN VSS
    DIRECTION INPUT ;
    USE GROUND ;
    PORT
      LAYER TOP_M ;
        RECT 858.75 6 861.25 879.6 ;
    END
  END VSS
  OBS
    LAYER GC SPACING 0 ;
      RECT 0 0 885.6 885.6 ;
    LAYER M1 SPACING 0 ;
      RECT 0 0 885.6 885.6 ;
    LAYER M2 SPACING 0 ;
      POLYGON 885.6 885.6 885.6 0 0 0 0 885.6 14.26 885.6 14.26 884.875 14.54 884.875 14.54 885.6 22.66 885.6 22.66 884.875 22.94 884.875 22.94 885.6 31.06 885.6 31.06 884.875 31.34 884.875 31.34 885.6 39.46 885.6 39.46 884.875 39.74 884.875 39.74 885.6 47.86 885.6 47.86 884.875 48.14 884.875 48.14 885.6 56.26 885.6 56.26 884.875 56.54 884.875 56.54 885.6 64.66 885.6 64.66 884.875 64.94 884.875 64.94 885.6 73.06 885.6 73.06 884.875 73.34 884.875 73.34 885.6 81.46 885.6 81.46 884.875 81.74 884.875 81.74 885.6 89.86 885.6 89.86 884.875 90.14 884.875 90.14 885.6 98.26 885.6 98.26 884.875 98.54 884.875 98.54 885.6 106.66 885.6 106.66 884.875 106.94 884.875 106.94 885.6 115.06 885.6 115.06 884.875 115.34 884.875 115.34 885.6 123.46 885.6 123.46 884.875 123.74 884.875 123.74 885.6 131.86 885.6 131.86 884.875 132.14 884.875 132.14 885.6 140.26 885.6 140.26 884.875 140.54 884.875 140.54 885.6 148.66 885.6 148.66 884.875 148.94 884.875 148.94 885.6 157.06 885.6 157.06 884.875 157.34 884.875 157.34 885.6 165.46 885.6 165.46 884.875 165.74 884.875 165.74 885.6 173.86 885.6 173.86 884.875 174.14 884.875 174.14 885.6 182.26 885.6 182.26 884.875 182.54 884.875 182.54 885.6 190.66 885.6 190.66 884.875 190.94 884.875 190.94 885.6 199.06 885.6 199.06 884.875 199.34 884.875 199.34 885.6 207.46 885.6 207.46 884.875 207.74 884.875 207.74 885.6 215.86 885.6 215.86 884.875 216.14 884.875 216.14 885.6 224.26 885.6 224.26 884.875 224.54 884.875 224.54 885.6 232.66 885.6 232.66 884.875 232.94 884.875 232.94 885.6 241.06 885.6 241.06 884.875 241.34 884.875 241.34 885.6 249.46 885.6 249.46 884.875 249.74 884.875 249.74 885.6 257.86 885.6 257.86 884.875 258.14 884.875 258.14 885.6 266.26 885.6 266.26 884.875 266.54 884.875 266.54 885.6 274.66 885.6 274.66 884.875 274.94 884.875 274.94 885.6 283.06 885.6 283.06 884.875 283.34 884.875 283.34 885.6 291.46 885.6 291.46 884.875 291.74 884.875 291.74 885.6 299.86 885.6 299.86 884.875 300.14 884.875 300.14 885.6 308.26 885.6 308.26 884.875 308.54 884.875 308.54 885.6 316.66 885.6 316.66 884.875 316.94 884.875 316.94 885.6 325.06 885.6 325.06 884.875 325.34 884.875 325.34 885.6 333.46 885.6 333.46 884.875 333.74 884.875 333.74 885.6 341.86 885.6 341.86 884.875 342.14 884.875 342.14 885.6 350.26 885.6 350.26 884.875 350.54 884.875 350.54 885.6 358.66 885.6 358.66 884.875 358.94 884.875 358.94 885.6 367.06 885.6 367.06 884.875 367.34 884.875 367.34 885.6 375.46 885.6 375.46 884.875 375.74 884.875 375.74 885.6 383.86 885.6 383.86 884.875 384.14 884.875 384.14 885.6 392.26 885.6 392.26 884.875 392.54 884.875 392.54 885.6 400.66 885.6 400.66 884.875 400.94 884.875 400.94 885.6 409.06 885.6 409.06 884.875 409.34 884.875 409.34 885.6 417.46 885.6 417.46 884.875 417.74 884.875 417.74 885.6 425.86 885.6 425.86 884.875 426.14 884.875 426.14 885.6 434.26 885.6 434.26 884.875 434.54 884.875 434.54 885.6 442.66 885.6 442.66 884.875 442.94 884.875 442.94 885.6 451.06 885.6 451.06 884.875 451.34 884.875 451.34 885.6 459.46 885.6 459.46 884.875 459.74 884.875 459.74 885.6 467.86 885.6 467.86 884.875 468.14 884.875 468.14 885.6 476.26 885.6 476.26 884.875 476.54 884.875 476.54 885.6 484.66 885.6 484.66 884.875 484.94 884.875 484.94 885.6 493.06 885.6 493.06 884.875 493.34 884.875 493.34 885.6 501.46 885.6 501.46 884.875 501.74 884.875 501.74 885.6 509.86 885.6 509.86 884.875 510.14 884.875 510.14 885.6 518.26 885.6 518.26 884.875 518.54 884.875 518.54 885.6 526.66 885.6 526.66 884.875 526.94 884.875 526.94 885.6 535.06 885.6 535.06 884.875 535.34 884.875 535.34 885.6 543.46 885.6 543.46 884.875 543.74 884.875 543.74 885.6 551.86 885.6 551.86 884.875 552.14 884.875 552.14 885.6 560.26 885.6 560.26 884.875 560.54 884.875 560.54 885.6 568.66 885.6 568.66 884.875 568.94 884.875 568.94 885.6 577.06 885.6 577.06 884.875 577.34 884.875 577.34 885.6 585.46 885.6 585.46 884.875 585.74 884.875 585.74 885.6 593.86 885.6 593.86 884.875 594.14 884.875 594.14 885.6 602.26 885.6 602.26 884.875 602.54 884.875 602.54 885.6 610.66 885.6 610.66 884.875 610.94 884.875 610.94 885.6 619.06 885.6 619.06 884.875 619.34 884.875 619.34 885.6 627.46 885.6 627.46 884.875 627.74 884.875 627.74 885.6 635.86 885.6 635.86 884.875 636.14 884.875 636.14 885.6 644.26 885.6 644.26 884.875 644.54 884.875 644.54 885.6 652.66 885.6 652.66 884.875 652.94 884.875 652.94 885.6 661.06 885.6 661.06 884.875 661.34 884.875 661.34 885.6 669.46 885.6 669.46 884.875 669.74 884.875 669.74 885.6 677.86 885.6 677.86 884.875 678.14 884.875 678.14 885.6 686.26 885.6 686.26 884.875 686.54 884.875 686.54 885.6 694.66 885.6 694.66 884.875 694.94 884.875 694.94 885.6 703.06 885.6 703.06 884.875 703.34 884.875 703.34 885.6 711.46 885.6 711.46 884.875 711.74 884.875 711.74 885.6 719.86 885.6 719.86 884.875 720.14 884.875 720.14 885.6 728.26 885.6 728.26 884.875 728.54 884.875 728.54 885.6 736.66 885.6 736.66 884.875 736.94 884.875 736.94 885.6 745.06 885.6 745.06 884.875 745.34 884.875 745.34 885.6 753.46 885.6 753.46 884.875 753.74 884.875 753.74 885.6 761.86 885.6 761.86 884.875 762.14 884.875 762.14 885.6 770.26 885.6 770.26 884.875 770.54 884.875 770.54 885.6 778.66 885.6 778.66 884.875 778.94 884.875 778.94 885.6 787.06 885.6 787.06 884.875 787.34 884.875 787.34 885.6 795.46 885.6 795.46 884.875 795.74 884.875 795.74 885.6 803.86 885.6 803.86 884.875 804.14 884.875 804.14 885.6 812.26 885.6 812.26 884.875 812.54 884.875 812.54 885.6 820.66 885.6 820.66 884.875 820.94 884.875 820.94 885.6 829.06 885.6 829.06 884.875 829.34 884.875 829.34 885.6 837.46 885.6 837.46 884.875 837.74 884.875 837.74 885.6 845.86 885.6 845.86 884.875 846.14 884.875 846.14 885.6 854.26 885.6 854.26 884.875 854.54 884.875 854.54 885.6 862.66 885.6 862.66 884.875 862.94 884.875 862.94 885.6 ;
    LAYER M3 SPACING 0 ;
      POLYGON 885.6 885.6 885.6 878.41 884.875 878.41 884.875 878.13 885.6 878.13 885.6 869.87 884.875 869.87 884.875 869.59 885.6 869.59 885.6 861.33 884.875 861.33 884.875 861.05 885.6 861.05 885.6 852.79 884.875 852.79 884.875 852.51 885.6 852.51 885.6 844.25 884.875 844.25 884.875 843.97 885.6 843.97 885.6 835.71 884.875 835.71 884.875 835.43 885.6 835.43 885.6 827.17 884.875 827.17 884.875 826.89 885.6 826.89 885.6 818.63 884.875 818.63 884.875 818.35 885.6 818.35 885.6 810.09 884.875 810.09 884.875 809.81 885.6 809.81 885.6 801.55 884.875 801.55 884.875 801.27 885.6 801.27 885.6 793.01 884.875 793.01 884.875 792.73 885.6 792.73 885.6 784.47 884.875 784.47 884.875 784.19 885.6 784.19 885.6 775.93 884.875 775.93 884.875 775.65 885.6 775.65 885.6 767.39 884.875 767.39 884.875 767.11 885.6 767.11 885.6 758.85 884.875 758.85 884.875 758.57 885.6 758.57 885.6 750.31 884.875 750.31 884.875 750.03 885.6 750.03 885.6 741.77 884.875 741.77 884.875 741.49 885.6 741.49 885.6 733.23 884.875 733.23 884.875 732.95 885.6 732.95 885.6 724.69 884.875 724.69 884.875 724.41 885.6 724.41 885.6 716.15 884.875 716.15 884.875 715.87 885.6 715.87 885.6 707.61 884.875 707.61 884.875 707.33 885.6 707.33 885.6 699.07 884.875 699.07 884.875 698.79 885.6 698.79 885.6 690.53 884.875 690.53 884.875 690.25 885.6 690.25 885.6 681.99 884.875 681.99 884.875 681.71 885.6 681.71 885.6 673.45 884.875 673.45 884.875 673.17 885.6 673.17 885.6 664.91 884.875 664.91 884.875 664.63 885.6 664.63 885.6 656.37 884.875 656.37 884.875 656.09 885.6 656.09 885.6 647.83 884.875 647.83 884.875 647.55 885.6 647.55 885.6 639.29 884.875 639.29 884.875 639.01 885.6 639.01 885.6 630.75 884.875 630.75 884.875 630.47 885.6 630.47 885.6 622.21 884.875 622.21 884.875 621.93 885.6 621.93 885.6 613.67 884.875 613.67 884.875 613.39 885.6 613.39 885.6 605.13 884.875 605.13 884.875 604.85 885.6 604.85 885.6 596.59 884.875 596.59 884.875 596.31 885.6 596.31 885.6 588.05 884.875 588.05 884.875 587.77 885.6 587.77 885.6 579.51 884.875 579.51 884.875 579.23 885.6 579.23 885.6 570.97 884.875 570.97 884.875 570.69 885.6 570.69 885.6 562.43 884.875 562.43 884.875 562.15 885.6 562.15 885.6 553.89 884.875 553.89 884.875 553.61 885.6 553.61 885.6 545.35 884.875 545.35 884.875 545.07 885.6 545.07 885.6 536.81 884.875 536.81 884.875 536.53 885.6 536.53 885.6 528.27 884.875 528.27 884.875 527.99 885.6 527.99 885.6 519.73 884.875 519.73 884.875 519.45 885.6 519.45 885.6 511.19 884.875 511.19 884.875 510.91 885.6 510.91 885.6 502.65 884.875 502.65 884.875 502.37 885.6 502.37 885.6 494.11 884.875 494.11 884.875 493.83 885.6 493.83 885.6 485.57 884.875 485.57 884.875 485.29 885.6 485.29 885.6 477.03 884.875 477.03 884.875 476.75 885.6 476.75 885.6 468.49 884.875 468.49 884.875 468.21 885.6 468.21 885.6 459.95 884.875 459.95 884.875 459.67 885.6 459.67 885.6 451.41 884.875 451.41 884.875 451.13 885.6 451.13 885.6 442.87 884.875 442.87 884.875 442.59 885.6 442.59 885.6 434.33 884.875 434.33 884.875 434.05 885.6 434.05 885.6 425.79 884.875 425.79 884.875 425.51 885.6 425.51 885.6 417.25 884.875 417.25 884.875 416.97 885.6 416.97 885.6 408.71 884.875 408.71 884.875 408.43 885.6 408.43 885.6 400.17 884.875 400.17 884.875 399.89 885.6 399.89 885.6 391.63 884.875 391.63 884.875 391.35 885.6 391.35 885.6 383.09 884.875 383.09 884.875 382.81 885.6 382.81 885.6 374.55 884.875 374.55 884.875 374.27 885.6 374.27 885.6 366.01 884.875 366.01 884.875 365.73 885.6 365.73 885.6 357.47 884.875 357.47 884.875 357.19 885.6 357.19 885.6 348.93 884.875 348.93 884.875 348.65 885.6 348.65 885.6 340.39 884.875 340.39 884.875 340.11 885.6 340.11 885.6 331.85 884.875 331.85 884.875 331.57 885.6 331.57 885.6 323.31 884.875 323.31 884.875 323.03 885.6 323.03 885.6 314.77 884.875 314.77 884.875 314.49 885.6 314.49 885.6 306.23 884.875 306.23 884.875 305.95 885.6 305.95 885.6 297.69 884.875 297.69 884.875 297.41 885.6 297.41 885.6 289.15 884.875 289.15 884.875 288.87 885.6 288.87 885.6 280.61 884.875 280.61 884.875 280.33 885.6 280.33 885.6 272.07 884.875 272.07 884.875 271.79 885.6 271.79 885.6 263.53 884.875 263.53 884.875 263.25 885.6 263.25 885.6 254.99 884.875 254.99 884.875 254.71 885.6 254.71 885.6 246.45 884.875 246.45 884.875 246.17 885.6 246.17 885.6 237.91 884.875 237.91 884.875 237.63 885.6 237.63 885.6 229.37 884.875 229.37 884.875 229.09 885.6 229.09 885.6 220.83 884.875 220.83 884.875 220.55 885.6 220.55 885.6 212.29 884.875 212.29 884.875 212.01 885.6 212.01 885.6 203.75 884.875 203.75 884.875 203.47 885.6 203.47 885.6 195.21 884.875 195.21 884.875 194.93 885.6 194.93 885.6 186.67 884.875 186.67 884.875 186.39 885.6 186.39 885.6 178.13 884.875 178.13 884.875 177.85 885.6 177.85 885.6 169.59 884.875 169.59 884.875 169.31 885.6 169.31 885.6 161.05 884.875 161.05 884.875 160.77 885.6 160.77 885.6 152.51 884.875 152.51 884.875 152.23 885.6 152.23 885.6 143.97 884.875 143.97 884.875 143.69 885.6 143.69 885.6 135.43 884.875 135.43 884.875 135.15 885.6 135.15 885.6 126.89 884.875 126.89 884.875 126.61 885.6 126.61 885.6 118.35 884.875 118.35 884.875 118.07 885.6 118.07 885.6 109.81 884.875 109.81 884.875 109.53 885.6 109.53 885.6 101.27 884.875 101.27 884.875 100.99 885.6 100.99 885.6 92.73 884.875 92.73 884.875 92.45 885.6 92.45 885.6 84.19 884.875 84.19 884.875 83.91 885.6 83.91 885.6 75.65 884.875 75.65 884.875 75.37 885.6 75.37 885.6 67.11 884.875 67.11 884.875 66.83 885.6 66.83 885.6 58.57 884.875 58.57 884.875 58.29 885.6 58.29 885.6 50.03 884.875 50.03 884.875 49.75 885.6 49.75 885.6 41.49 884.875 41.49 884.875 41.21 885.6 41.21 885.6 32.95 884.875 32.95 884.875 32.67 885.6 32.67 885.6 24.41 884.875 24.41 884.875 24.13 885.6 24.13 885.6 15.87 884.875 15.87 884.875 15.59 885.6 15.59 885.6 0 0 0 0 885.6 ;
    LAYER TOP_M SPACING 0 ;
      POLYGON 885.6 885.6 885.6 879.6 858.75 879.6 858.75 873.6 828.75 873.6 828.75 12 831.25 12 831.25 873.6 858.75 873.6 858.75 6 861.25 6 861.25 879.6 885.6 879.6 885.6 0 0 0 0 885.6 ;
    LAYER WN SPACING 0 ;
      RECT 0 0 885.6 885.6 ;
    LAYER XP SPACING 0 ;
      RECT 0 0 885.6 885.6 ;
    LAYER XN SPACING 0 ;
      RECT 0 0 885.6 885.6 ;
    LAYER M3 ;
      POLYGON 885.32 885.32 885.32 878.69 884.595 878.69 884.595 877.85 885.32 877.85 885.32 870.15 884.595 870.15 884.595 869.31 885.32 869.31 885.32 861.61 884.595 861.61 884.595 860.77 885.32 860.77 885.32 853.07 884.595 853.07 884.595 852.23 885.32 852.23 885.32 844.53 884.595 844.53 884.595 843.69 885.32 843.69 885.32 835.99 884.595 835.99 884.595 835.15 885.32 835.15 885.32 827.45 884.595 827.45 884.595 826.61 885.32 826.61 885.32 818.91 884.595 818.91 884.595 818.07 885.32 818.07 885.32 810.37 884.595 810.37 884.595 809.53 885.32 809.53 885.32 801.83 884.595 801.83 884.595 800.99 885.32 800.99 885.32 793.29 884.595 793.29 884.595 792.45 885.32 792.45 885.32 784.75 884.595 784.75 884.595 783.91 885.32 783.91 885.32 776.21 884.595 776.21 884.595 775.37 885.32 775.37 885.32 767.67 884.595 767.67 884.595 766.83 885.32 766.83 885.32 759.13 884.595 759.13 884.595 758.29 885.32 758.29 885.32 750.59 884.595 750.59 884.595 749.75 885.32 749.75 885.32 742.05 884.595 742.05 884.595 741.21 885.32 741.21 885.32 733.51 884.595 733.51 884.595 732.67 885.32 732.67 885.32 724.97 884.595 724.97 884.595 724.13 885.32 724.13 885.32 716.43 884.595 716.43 884.595 715.59 885.32 715.59 885.32 707.89 884.595 707.89 884.595 707.05 885.32 707.05 885.32 699.35 884.595 699.35 884.595 698.51 885.32 698.51 885.32 690.81 884.595 690.81 884.595 689.97 885.32 689.97 885.32 682.27 884.595 682.27 884.595 681.43 885.32 681.43 885.32 673.73 884.595 673.73 884.595 672.89 885.32 672.89 885.32 665.19 884.595 665.19 884.595 664.35 885.32 664.35 885.32 656.65 884.595 656.65 884.595 655.81 885.32 655.81 885.32 648.11 884.595 648.11 884.595 647.27 885.32 647.27 885.32 639.57 884.595 639.57 884.595 638.73 885.32 638.73 885.32 631.03 884.595 631.03 884.595 630.19 885.32 630.19 885.32 622.49 884.595 622.49 884.595 621.65 885.32 621.65 885.32 613.95 884.595 613.95 884.595 613.11 885.32 613.11 885.32 605.41 884.595 605.41 884.595 604.57 885.32 604.57 885.32 596.87 884.595 596.87 884.595 596.03 885.32 596.03 885.32 588.33 884.595 588.33 884.595 587.49 885.32 587.49 885.32 579.79 884.595 579.79 884.595 578.95 885.32 578.95 885.32 571.25 884.595 571.25 884.595 570.41 885.32 570.41 885.32 562.71 884.595 562.71 884.595 561.87 885.32 561.87 885.32 554.17 884.595 554.17 884.595 553.33 885.32 553.33 885.32 545.63 884.595 545.63 884.595 544.79 885.32 544.79 885.32 537.09 884.595 537.09 884.595 536.25 885.32 536.25 885.32 528.55 884.595 528.55 884.595 527.71 885.32 527.71 885.32 520.01 884.595 520.01 884.595 519.17 885.32 519.17 885.32 511.47 884.595 511.47 884.595 510.63 885.32 510.63 885.32 502.93 884.595 502.93 884.595 502.09 885.32 502.09 885.32 494.39 884.595 494.39 884.595 493.55 885.32 493.55 885.32 485.85 884.595 485.85 884.595 485.01 885.32 485.01 885.32 477.31 884.595 477.31 884.595 476.47 885.32 476.47 885.32 468.77 884.595 468.77 884.595 467.93 885.32 467.93 885.32 460.23 884.595 460.23 884.595 459.39 885.32 459.39 885.32 451.69 884.595 451.69 884.595 450.85 885.32 450.85 885.32 443.15 884.595 443.15 884.595 442.31 885.32 442.31 885.32 434.61 884.595 434.61 884.595 433.77 885.32 433.77 885.32 426.07 884.595 426.07 884.595 425.23 885.32 425.23 885.32 417.53 884.595 417.53 884.595 416.69 885.32 416.69 885.32 408.99 884.595 408.99 884.595 408.15 885.32 408.15 885.32 400.45 884.595 400.45 884.595 399.61 885.32 399.61 885.32 391.91 884.595 391.91 884.595 391.07 885.32 391.07 885.32 383.37 884.595 383.37 884.595 382.53 885.32 382.53 885.32 374.83 884.595 374.83 884.595 373.99 885.32 373.99 885.32 366.29 884.595 366.29 884.595 365.45 885.32 365.45 885.32 357.75 884.595 357.75 884.595 356.91 885.32 356.91 885.32 349.21 884.595 349.21 884.595 348.37 885.32 348.37 885.32 340.67 884.595 340.67 884.595 339.83 885.32 339.83 885.32 332.13 884.595 332.13 884.595 331.29 885.32 331.29 885.32 323.59 884.595 323.59 884.595 322.75 885.32 322.75 885.32 315.05 884.595 315.05 884.595 314.21 885.32 314.21 885.32 306.51 884.595 306.51 884.595 305.67 885.32 305.67 885.32 297.97 884.595 297.97 884.595 297.13 885.32 297.13 885.32 289.43 884.595 289.43 884.595 288.59 885.32 288.59 885.32 280.89 884.595 280.89 884.595 280.05 885.32 280.05 885.32 272.35 884.595 272.35 884.595 271.51 885.32 271.51 885.32 263.81 884.595 263.81 884.595 262.97 885.32 262.97 885.32 255.27 884.595 255.27 884.595 254.43 885.32 254.43 885.32 246.73 884.595 246.73 884.595 245.89 885.32 245.89 885.32 238.19 884.595 238.19 884.595 237.35 885.32 237.35 885.32 229.65 884.595 229.65 884.595 228.81 885.32 228.81 885.32 221.11 884.595 221.11 884.595 220.27 885.32 220.27 885.32 212.57 884.595 212.57 884.595 211.73 885.32 211.73 885.32 204.03 884.595 204.03 884.595 203.19 885.32 203.19 885.32 195.49 884.595 195.49 884.595 194.65 885.32 194.65 885.32 186.95 884.595 186.95 884.595 186.11 885.32 186.11 885.32 178.41 884.595 178.41 884.595 177.57 885.32 177.57 885.32 169.87 884.595 169.87 884.595 169.03 885.32 169.03 885.32 161.33 884.595 161.33 884.595 160.49 885.32 160.49 885.32 152.79 884.595 152.79 884.595 151.95 885.32 151.95 885.32 144.25 884.595 144.25 884.595 143.41 885.32 143.41 885.32 135.71 884.595 135.71 884.595 134.87 885.32 134.87 885.32 127.17 884.595 127.17 884.595 126.33 885.32 126.33 885.32 118.63 884.595 118.63 884.595 117.79 885.32 117.79 885.32 110.09 884.595 110.09 884.595 109.25 885.32 109.25 885.32 101.55 884.595 101.55 884.595 100.71 885.32 100.71 885.32 93.01 884.595 93.01 884.595 92.17 885.32 92.17 885.32 84.47 884.595 84.47 884.595 83.63 885.32 83.63 885.32 75.93 884.595 75.93 884.595 75.09 885.32 75.09 885.32 67.39 884.595 67.39 884.595 66.55 885.32 66.55 885.32 58.85 884.595 58.85 884.595 58.01 885.32 58.01 885.32 50.31 884.595 50.31 884.595 49.47 885.32 49.47 885.32 41.77 884.595 41.77 884.595 40.93 885.32 40.93 885.32 33.23 884.595 33.23 884.595 32.39 885.32 32.39 885.32 24.69 884.595 24.69 884.595 23.85 885.32 23.85 885.32 16.15 884.595 16.15 884.595 15.31 885.32 15.31 885.32 0.28 0.28 0.28 0.28 885.32 ;
    LAYER M2 ;
      POLYGON 885.32 885.32 885.32 0.28 0.28 0.28 0.28 885.32 13.98 885.32 13.98 884.595 14.82 884.595 14.82 885.32 22.38 885.32 22.38 884.595 23.22 884.595 23.22 885.32 30.78 885.32 30.78 884.595 31.62 884.595 31.62 885.32 39.18 885.32 39.18 884.595 40.02 884.595 40.02 885.32 47.58 885.32 47.58 884.595 48.42 884.595 48.42 885.32 55.98 885.32 55.98 884.595 56.82 884.595 56.82 885.32 64.38 885.32 64.38 884.595 65.22 884.595 65.22 885.32 72.78 885.32 72.78 884.595 73.62 884.595 73.62 885.32 81.18 885.32 81.18 884.595 82.02 884.595 82.02 885.32 89.58 885.32 89.58 884.595 90.42 884.595 90.42 885.32 97.98 885.32 97.98 884.595 98.82 884.595 98.82 885.32 106.38 885.32 106.38 884.595 107.22 884.595 107.22 885.32 114.78 885.32 114.78 884.595 115.62 884.595 115.62 885.32 123.18 885.32 123.18 884.595 124.02 884.595 124.02 885.32 131.58 885.32 131.58 884.595 132.42 884.595 132.42 885.32 139.98 885.32 139.98 884.595 140.82 884.595 140.82 885.32 148.38 885.32 148.38 884.595 149.22 884.595 149.22 885.32 156.78 885.32 156.78 884.595 157.62 884.595 157.62 885.32 165.18 885.32 165.18 884.595 166.02 884.595 166.02 885.32 173.58 885.32 173.58 884.595 174.42 884.595 174.42 885.32 181.98 885.32 181.98 884.595 182.82 884.595 182.82 885.32 190.38 885.32 190.38 884.595 191.22 884.595 191.22 885.32 198.78 885.32 198.78 884.595 199.62 884.595 199.62 885.32 207.18 885.32 207.18 884.595 208.02 884.595 208.02 885.32 215.58 885.32 215.58 884.595 216.42 884.595 216.42 885.32 223.98 885.32 223.98 884.595 224.82 884.595 224.82 885.32 232.38 885.32 232.38 884.595 233.22 884.595 233.22 885.32 240.78 885.32 240.78 884.595 241.62 884.595 241.62 885.32 249.18 885.32 249.18 884.595 250.02 884.595 250.02 885.32 257.58 885.32 257.58 884.595 258.42 884.595 258.42 885.32 265.98 885.32 265.98 884.595 266.82 884.595 266.82 885.32 274.38 885.32 274.38 884.595 275.22 884.595 275.22 885.32 282.78 885.32 282.78 884.595 283.62 884.595 283.62 885.32 291.18 885.32 291.18 884.595 292.02 884.595 292.02 885.32 299.58 885.32 299.58 884.595 300.42 884.595 300.42 885.32 307.98 885.32 307.98 884.595 308.82 884.595 308.82 885.32 316.38 885.32 316.38 884.595 317.22 884.595 317.22 885.32 324.78 885.32 324.78 884.595 325.62 884.595 325.62 885.32 333.18 885.32 333.18 884.595 334.02 884.595 334.02 885.32 341.58 885.32 341.58 884.595 342.42 884.595 342.42 885.32 349.98 885.32 349.98 884.595 350.82 884.595 350.82 885.32 358.38 885.32 358.38 884.595 359.22 884.595 359.22 885.32 366.78 885.32 366.78 884.595 367.62 884.595 367.62 885.32 375.18 885.32 375.18 884.595 376.02 884.595 376.02 885.32 383.58 885.32 383.58 884.595 384.42 884.595 384.42 885.32 391.98 885.32 391.98 884.595 392.82 884.595 392.82 885.32 400.38 885.32 400.38 884.595 401.22 884.595 401.22 885.32 408.78 885.32 408.78 884.595 409.62 884.595 409.62 885.32 417.18 885.32 417.18 884.595 418.02 884.595 418.02 885.32 425.58 885.32 425.58 884.595 426.42 884.595 426.42 885.32 433.98 885.32 433.98 884.595 434.82 884.595 434.82 885.32 442.38 885.32 442.38 884.595 443.22 884.595 443.22 885.32 450.78 885.32 450.78 884.595 451.62 884.595 451.62 885.32 459.18 885.32 459.18 884.595 460.02 884.595 460.02 885.32 467.58 885.32 467.58 884.595 468.42 884.595 468.42 885.32 475.98 885.32 475.98 884.595 476.82 884.595 476.82 885.32 484.38 885.32 484.38 884.595 485.22 884.595 485.22 885.32 492.78 885.32 492.78 884.595 493.62 884.595 493.62 885.32 501.18 885.32 501.18 884.595 502.02 884.595 502.02 885.32 509.58 885.32 509.58 884.595 510.42 884.595 510.42 885.32 517.98 885.32 517.98 884.595 518.82 884.595 518.82 885.32 526.38 885.32 526.38 884.595 527.22 884.595 527.22 885.32 534.78 885.32 534.78 884.595 535.62 884.595 535.62 885.32 543.18 885.32 543.18 884.595 544.02 884.595 544.02 885.32 551.58 885.32 551.58 884.595 552.42 884.595 552.42 885.32 559.98 885.32 559.98 884.595 560.82 884.595 560.82 885.32 568.38 885.32 568.38 884.595 569.22 884.595 569.22 885.32 576.78 885.32 576.78 884.595 577.62 884.595 577.62 885.32 585.18 885.32 585.18 884.595 586.02 884.595 586.02 885.32 593.58 885.32 593.58 884.595 594.42 884.595 594.42 885.32 601.98 885.32 601.98 884.595 602.82 884.595 602.82 885.32 610.38 885.32 610.38 884.595 611.22 884.595 611.22 885.32 618.78 885.32 618.78 884.595 619.62 884.595 619.62 885.32 627.18 885.32 627.18 884.595 628.02 884.595 628.02 885.32 635.58 885.32 635.58 884.595 636.42 884.595 636.42 885.32 643.98 885.32 643.98 884.595 644.82 884.595 644.82 885.32 652.38 885.32 652.38 884.595 653.22 884.595 653.22 885.32 660.78 885.32 660.78 884.595 661.62 884.595 661.62 885.32 669.18 885.32 669.18 884.595 670.02 884.595 670.02 885.32 677.58 885.32 677.58 884.595 678.42 884.595 678.42 885.32 685.98 885.32 685.98 884.595 686.82 884.595 686.82 885.32 694.38 885.32 694.38 884.595 695.22 884.595 695.22 885.32 702.78 885.32 702.78 884.595 703.62 884.595 703.62 885.32 711.18 885.32 711.18 884.595 712.02 884.595 712.02 885.32 719.58 885.32 719.58 884.595 720.42 884.595 720.42 885.32 727.98 885.32 727.98 884.595 728.82 884.595 728.82 885.32 736.38 885.32 736.38 884.595 737.22 884.595 737.22 885.32 744.78 885.32 744.78 884.595 745.62 884.595 745.62 885.32 753.18 885.32 753.18 884.595 754.02 884.595 754.02 885.32 761.58 885.32 761.58 884.595 762.42 884.595 762.42 885.32 769.98 885.32 769.98 884.595 770.82 884.595 770.82 885.32 778.38 885.32 778.38 884.595 779.22 884.595 779.22 885.32 786.78 885.32 786.78 884.595 787.62 884.595 787.62 885.32 795.18 885.32 795.18 884.595 796.02 884.595 796.02 885.32 803.58 885.32 803.58 884.595 804.42 884.595 804.42 885.32 811.98 885.32 811.98 884.595 812.82 884.595 812.82 885.32 820.38 885.32 820.38 884.595 821.22 884.595 821.22 885.32 828.78 885.32 828.78 884.595 829.62 884.595 829.62 885.32 837.18 885.32 837.18 884.595 838.02 884.595 838.02 885.32 845.58 885.32 845.58 884.595 846.42 884.595 846.42 885.32 853.98 885.32 853.98 884.595 854.82 884.595 854.82 885.32 862.38 885.32 862.38 884.595 863.22 884.595 863.22 885.32 ;
    LAYER TOP_M ;
      POLYGON 885.14 885.14 885.14 880.06 858.29 880.06 858.29 874.06 828.29 874.06 828.29 11.54 831.71 11.54 831.71 874.06 858.29 874.06 858.29 5.54 861.71 5.54 861.71 880.06 885.14 880.06 885.14 0.46 0.46 0.46 0.46 885.14 ;
    LAYER M1 ;
      RECT 0.23 0.23 885.37 885.37 ;
    LAYER WN ;
      RECT 1.4 1.4 884.2 884.2 ;
    LAYER GC ;
      RECT 0.25 0.25 885.35 885.35 ;
    LAYER XP ;
      RECT 0.44 0.44 885.16 885.16 ;
    LAYER XN ;
      RECT 0.44 0.44 885.16 885.16 ;
    LAYER V3 ;
      RECT 165.47 884.85 165.73 885.11 ;
      RECT 884.51 349.18 884.77 349.44 ;
      RECT 884.51 348.66 884.77 348.92 ;
    LAYER TOP_V ;
      RECT 860.53 878.84 860.89 879.2 ;
      RECT 859.82 878.84 860.18 879.2 ;
      RECT 859.11 878.84 859.47 879.2 ;
      RECT 860.53 878.13 860.89 878.49 ;
      RECT 859.82 878.13 860.18 878.49 ;
      RECT 859.11 878.13 859.47 878.49 ;
      RECT 860.53 877.42 860.89 877.78 ;
      RECT 859.82 877.42 860.18 877.78 ;
      RECT 859.11 877.42 859.47 877.78 ;
      RECT 860.53 876.71 860.89 877.07 ;
      RECT 859.82 876.71 860.18 877.07 ;
      RECT 859.11 876.71 859.47 877.07 ;
      RECT 860.53 876 860.89 876.36 ;
      RECT 859.82 876 860.18 876.36 ;
      RECT 859.11 876 859.47 876.36 ;
      RECT 830.53 872.84 830.89 873.2 ;
      RECT 829.82 872.84 830.18 873.2 ;
      RECT 829.11 872.84 829.47 873.2 ;
      RECT 830.53 872.13 830.89 872.49 ;
      RECT 829.82 872.13 830.18 872.49 ;
      RECT 829.11 872.13 829.47 872.49 ;
      RECT 830.53 871.42 830.89 871.78 ;
      RECT 829.82 871.42 830.18 871.78 ;
      RECT 829.11 871.42 829.47 871.78 ;
      RECT 830.53 870.71 830.89 871.07 ;
      RECT 829.82 870.71 830.18 871.07 ;
      RECT 829.11 870.71 829.47 871.07 ;
      RECT 830.53 870 830.89 870.36 ;
      RECT 829.82 870 830.18 870.36 ;
      RECT 829.11 870 829.47 870.36 ;
      RECT 860.53 865.42 860.89 865.78 ;
      RECT 859.82 865.42 860.18 865.78 ;
      RECT 859.11 865.42 859.47 865.78 ;
      RECT 830.53 859.82 830.89 860.18 ;
      RECT 829.82 859.82 830.18 860.18 ;
      RECT 829.11 859.82 829.47 860.18 ;
      RECT 860.53 854.22 860.89 854.58 ;
      RECT 859.82 854.22 860.18 854.58 ;
      RECT 859.11 854.22 859.47 854.58 ;
      RECT 830.53 848.62 830.89 848.98 ;
      RECT 829.82 848.62 830.18 848.98 ;
      RECT 829.11 848.62 829.47 848.98 ;
      RECT 860.53 843.375 860.89 843.735 ;
      RECT 859.82 843.375 860.18 843.735 ;
      RECT 859.11 843.375 859.47 843.735 ;
      RECT 860.53 842.665 860.89 843.025 ;
      RECT 859.82 842.665 860.18 843.025 ;
      RECT 859.11 842.665 859.47 843.025 ;
      RECT 830.53 837.42 830.89 837.78 ;
      RECT 829.82 837.42 830.18 837.78 ;
      RECT 829.11 837.42 829.47 837.78 ;
      RECT 860.53 831.82 860.89 832.18 ;
      RECT 859.82 831.82 860.18 832.18 ;
      RECT 859.11 831.82 859.47 832.18 ;
      RECT 830.53 826.22 830.89 826.58 ;
      RECT 829.82 826.22 830.18 826.58 ;
      RECT 829.11 826.22 829.47 826.58 ;
      RECT 860.53 820.62 860.89 820.98 ;
      RECT 859.82 820.62 860.18 820.98 ;
      RECT 859.11 820.62 859.47 820.98 ;
      RECT 830.53 815.375 830.89 815.735 ;
      RECT 829.82 815.375 830.18 815.735 ;
      RECT 829.11 815.375 829.47 815.735 ;
      RECT 830.53 814.665 830.89 815.025 ;
      RECT 829.82 814.665 830.18 815.025 ;
      RECT 829.11 814.665 829.47 815.025 ;
      RECT 860.53 809.42 860.89 809.78 ;
      RECT 859.82 809.42 860.18 809.78 ;
      RECT 859.11 809.42 859.47 809.78 ;
      RECT 830.53 803.82 830.89 804.18 ;
      RECT 829.82 803.82 830.18 804.18 ;
      RECT 829.11 803.82 829.47 804.18 ;
      RECT 860.53 798.22 860.89 798.58 ;
      RECT 859.82 798.22 860.18 798.58 ;
      RECT 859.11 798.22 859.47 798.58 ;
      RECT 830.53 792.62 830.89 792.98 ;
      RECT 829.82 792.62 830.18 792.98 ;
      RECT 829.11 792.62 829.47 792.98 ;
      RECT 860.53 787.375 860.89 787.735 ;
      RECT 859.82 787.375 860.18 787.735 ;
      RECT 859.11 787.375 859.47 787.735 ;
      RECT 860.53 786.665 860.89 787.025 ;
      RECT 859.82 786.665 860.18 787.025 ;
      RECT 859.11 786.665 859.47 787.025 ;
      RECT 830.53 781.42 830.89 781.78 ;
      RECT 829.82 781.42 830.18 781.78 ;
      RECT 829.11 781.42 829.47 781.78 ;
      RECT 860.53 775.82 860.89 776.18 ;
      RECT 859.82 775.82 860.18 776.18 ;
      RECT 859.11 775.82 859.47 776.18 ;
      RECT 830.53 770.22 830.89 770.58 ;
      RECT 829.82 770.22 830.18 770.58 ;
      RECT 829.11 770.22 829.47 770.58 ;
      RECT 860.53 764.62 860.89 764.98 ;
      RECT 859.82 764.62 860.18 764.98 ;
      RECT 859.11 764.62 859.47 764.98 ;
      RECT 830.53 759.375 830.89 759.735 ;
      RECT 829.82 759.375 830.18 759.735 ;
      RECT 829.11 759.375 829.47 759.735 ;
      RECT 830.53 758.665 830.89 759.025 ;
      RECT 829.82 758.665 830.18 759.025 ;
      RECT 829.11 758.665 829.47 759.025 ;
      RECT 860.53 753.42 860.89 753.78 ;
      RECT 859.82 753.42 860.18 753.78 ;
      RECT 859.11 753.42 859.47 753.78 ;
      RECT 830.53 747.82 830.89 748.18 ;
      RECT 829.82 747.82 830.18 748.18 ;
      RECT 829.11 747.82 829.47 748.18 ;
      RECT 860.53 742.22 860.89 742.58 ;
      RECT 859.82 742.22 860.18 742.58 ;
      RECT 859.11 742.22 859.47 742.58 ;
      RECT 830.53 736.62 830.89 736.98 ;
      RECT 829.82 736.62 830.18 736.98 ;
      RECT 829.11 736.62 829.47 736.98 ;
      RECT 860.53 731.375 860.89 731.735 ;
      RECT 859.82 731.375 860.18 731.735 ;
      RECT 859.11 731.375 859.47 731.735 ;
      RECT 860.53 730.665 860.89 731.025 ;
      RECT 859.82 730.665 860.18 731.025 ;
      RECT 859.11 730.665 859.47 731.025 ;
      RECT 830.53 725.42 830.89 725.78 ;
      RECT 829.82 725.42 830.18 725.78 ;
      RECT 829.11 725.42 829.47 725.78 ;
      RECT 860.53 719.82 860.89 720.18 ;
      RECT 859.82 719.82 860.18 720.18 ;
      RECT 859.11 719.82 859.47 720.18 ;
      RECT 830.53 714.22 830.89 714.58 ;
      RECT 829.82 714.22 830.18 714.58 ;
      RECT 829.11 714.22 829.47 714.58 ;
      RECT 860.53 708.62 860.89 708.98 ;
      RECT 859.82 708.62 860.18 708.98 ;
      RECT 859.11 708.62 859.47 708.98 ;
      RECT 830.53 703.375 830.89 703.735 ;
      RECT 829.82 703.375 830.18 703.735 ;
      RECT 829.11 703.375 829.47 703.735 ;
      RECT 830.53 702.665 830.89 703.025 ;
      RECT 829.82 702.665 830.18 703.025 ;
      RECT 829.11 702.665 829.47 703.025 ;
      RECT 860.53 697.42 860.89 697.78 ;
      RECT 859.82 697.42 860.18 697.78 ;
      RECT 859.11 697.42 859.47 697.78 ;
      RECT 830.53 691.82 830.89 692.18 ;
      RECT 829.82 691.82 830.18 692.18 ;
      RECT 829.11 691.82 829.47 692.18 ;
      RECT 860.53 686.22 860.89 686.58 ;
      RECT 859.82 686.22 860.18 686.58 ;
      RECT 859.11 686.22 859.47 686.58 ;
      RECT 830.53 680.62 830.89 680.98 ;
      RECT 829.82 680.62 830.18 680.98 ;
      RECT 829.11 680.62 829.47 680.98 ;
      RECT 860.53 675.375 860.89 675.735 ;
      RECT 859.82 675.375 860.18 675.735 ;
      RECT 859.11 675.375 859.47 675.735 ;
      RECT 860.53 674.665 860.89 675.025 ;
      RECT 859.82 674.665 860.18 675.025 ;
      RECT 859.11 674.665 859.47 675.025 ;
      RECT 830.53 669.42 830.89 669.78 ;
      RECT 829.82 669.42 830.18 669.78 ;
      RECT 829.11 669.42 829.47 669.78 ;
      RECT 860.53 663.82 860.89 664.18 ;
      RECT 859.82 663.82 860.18 664.18 ;
      RECT 859.11 663.82 859.47 664.18 ;
      RECT 830.53 658.22 830.89 658.58 ;
      RECT 829.82 658.22 830.18 658.58 ;
      RECT 829.11 658.22 829.47 658.58 ;
      RECT 860.53 652.62 860.89 652.98 ;
      RECT 859.82 652.62 860.18 652.98 ;
      RECT 859.11 652.62 859.47 652.98 ;
      RECT 830.53 647.375 830.89 647.735 ;
      RECT 829.82 647.375 830.18 647.735 ;
      RECT 829.11 647.375 829.47 647.735 ;
      RECT 830.53 646.665 830.89 647.025 ;
      RECT 829.82 646.665 830.18 647.025 ;
      RECT 829.11 646.665 829.47 647.025 ;
      RECT 860.53 641.42 860.89 641.78 ;
      RECT 859.82 641.42 860.18 641.78 ;
      RECT 859.11 641.42 859.47 641.78 ;
      RECT 830.53 635.82 830.89 636.18 ;
      RECT 829.82 635.82 830.18 636.18 ;
      RECT 829.11 635.82 829.47 636.18 ;
      RECT 860.53 630.22 860.89 630.58 ;
      RECT 859.82 630.22 860.18 630.58 ;
      RECT 859.11 630.22 859.47 630.58 ;
      RECT 830.53 624.62 830.89 624.98 ;
      RECT 829.82 624.62 830.18 624.98 ;
      RECT 829.11 624.62 829.47 624.98 ;
      RECT 860.53 619.375 860.89 619.735 ;
      RECT 859.82 619.375 860.18 619.735 ;
      RECT 859.11 619.375 859.47 619.735 ;
      RECT 860.53 618.665 860.89 619.025 ;
      RECT 859.82 618.665 860.18 619.025 ;
      RECT 859.11 618.665 859.47 619.025 ;
      RECT 830.53 613.42 830.89 613.78 ;
      RECT 829.82 613.42 830.18 613.78 ;
      RECT 829.11 613.42 829.47 613.78 ;
      RECT 860.53 607.82 860.89 608.18 ;
      RECT 859.82 607.82 860.18 608.18 ;
      RECT 859.11 607.82 859.47 608.18 ;
      RECT 830.53 602.22 830.89 602.58 ;
      RECT 829.82 602.22 830.18 602.58 ;
      RECT 829.11 602.22 829.47 602.58 ;
      RECT 860.53 596.62 860.89 596.98 ;
      RECT 859.82 596.62 860.18 596.98 ;
      RECT 859.11 596.62 859.47 596.98 ;
      RECT 830.53 591.375 830.89 591.735 ;
      RECT 829.82 591.375 830.18 591.735 ;
      RECT 829.11 591.375 829.47 591.735 ;
      RECT 830.53 590.665 830.89 591.025 ;
      RECT 829.82 590.665 830.18 591.025 ;
      RECT 829.11 590.665 829.47 591.025 ;
      RECT 860.53 585.42 860.89 585.78 ;
      RECT 859.82 585.42 860.18 585.78 ;
      RECT 859.11 585.42 859.47 585.78 ;
      RECT 830.53 579.82 830.89 580.18 ;
      RECT 829.82 579.82 830.18 580.18 ;
      RECT 829.11 579.82 829.47 580.18 ;
      RECT 860.53 574.22 860.89 574.58 ;
      RECT 859.82 574.22 860.18 574.58 ;
      RECT 859.11 574.22 859.47 574.58 ;
      RECT 830.53 568.62 830.89 568.98 ;
      RECT 829.82 568.62 830.18 568.98 ;
      RECT 829.11 568.62 829.47 568.98 ;
      RECT 860.53 563.375 860.89 563.735 ;
      RECT 859.82 563.375 860.18 563.735 ;
      RECT 859.11 563.375 859.47 563.735 ;
      RECT 860.53 562.665 860.89 563.025 ;
      RECT 859.82 562.665 860.18 563.025 ;
      RECT 859.11 562.665 859.47 563.025 ;
      RECT 830.53 557.42 830.89 557.78 ;
      RECT 829.82 557.42 830.18 557.78 ;
      RECT 829.11 557.42 829.47 557.78 ;
      RECT 860.53 551.82 860.89 552.18 ;
      RECT 859.82 551.82 860.18 552.18 ;
      RECT 859.11 551.82 859.47 552.18 ;
      RECT 830.53 546.22 830.89 546.58 ;
      RECT 829.82 546.22 830.18 546.58 ;
      RECT 829.11 546.22 829.47 546.58 ;
      RECT 860.53 540.62 860.89 540.98 ;
      RECT 859.82 540.62 860.18 540.98 ;
      RECT 859.11 540.62 859.47 540.98 ;
      RECT 830.53 535.375 830.89 535.735 ;
      RECT 829.82 535.375 830.18 535.735 ;
      RECT 829.11 535.375 829.47 535.735 ;
      RECT 830.53 534.665 830.89 535.025 ;
      RECT 829.82 534.665 830.18 535.025 ;
      RECT 829.11 534.665 829.47 535.025 ;
      RECT 860.53 529.42 860.89 529.78 ;
      RECT 859.82 529.42 860.18 529.78 ;
      RECT 859.11 529.42 859.47 529.78 ;
      RECT 830.53 523.82 830.89 524.18 ;
      RECT 829.82 523.82 830.18 524.18 ;
      RECT 829.11 523.82 829.47 524.18 ;
      RECT 860.53 518.22 860.89 518.58 ;
      RECT 859.82 518.22 860.18 518.58 ;
      RECT 859.11 518.22 859.47 518.58 ;
      RECT 830.53 512.62 830.89 512.98 ;
      RECT 829.82 512.62 830.18 512.98 ;
      RECT 829.11 512.62 829.47 512.98 ;
      RECT 860.53 507.375 860.89 507.735 ;
      RECT 859.82 507.375 860.18 507.735 ;
      RECT 859.11 507.375 859.47 507.735 ;
      RECT 860.53 506.665 860.89 507.025 ;
      RECT 859.82 506.665 860.18 507.025 ;
      RECT 859.11 506.665 859.47 507.025 ;
      RECT 830.53 501.42 830.89 501.78 ;
      RECT 829.82 501.42 830.18 501.78 ;
      RECT 829.11 501.42 829.47 501.78 ;
      RECT 860.53 495.82 860.89 496.18 ;
      RECT 859.82 495.82 860.18 496.18 ;
      RECT 859.11 495.82 859.47 496.18 ;
      RECT 830.53 490.22 830.89 490.58 ;
      RECT 829.82 490.22 830.18 490.58 ;
      RECT 829.11 490.22 829.47 490.58 ;
      RECT 860.53 484.62 860.89 484.98 ;
      RECT 859.82 484.62 860.18 484.98 ;
      RECT 859.11 484.62 859.47 484.98 ;
      RECT 830.53 479.375 830.89 479.735 ;
      RECT 829.82 479.375 830.18 479.735 ;
      RECT 829.11 479.375 829.47 479.735 ;
      RECT 830.53 478.665 830.89 479.025 ;
      RECT 829.82 478.665 830.18 479.025 ;
      RECT 829.11 478.665 829.47 479.025 ;
      RECT 860.53 473.42 860.89 473.78 ;
      RECT 859.82 473.42 860.18 473.78 ;
      RECT 859.11 473.42 859.47 473.78 ;
      RECT 830.53 467.82 830.89 468.18 ;
      RECT 829.82 467.82 830.18 468.18 ;
      RECT 829.11 467.82 829.47 468.18 ;
      RECT 860.53 462.22 860.89 462.58 ;
      RECT 859.82 462.22 860.18 462.58 ;
      RECT 859.11 462.22 859.47 462.58 ;
      RECT 830.53 456.62 830.89 456.98 ;
      RECT 829.82 456.62 830.18 456.98 ;
      RECT 829.11 456.62 829.47 456.98 ;
      RECT 860.53 451.375 860.89 451.735 ;
      RECT 859.82 451.375 860.18 451.735 ;
      RECT 859.11 451.375 859.47 451.735 ;
      RECT 860.53 450.665 860.89 451.025 ;
      RECT 859.82 450.665 860.18 451.025 ;
      RECT 859.11 450.665 859.47 451.025 ;
      RECT 830.53 445.42 830.89 445.78 ;
      RECT 829.82 445.42 830.18 445.78 ;
      RECT 829.11 445.42 829.47 445.78 ;
      RECT 860.53 439.82 860.89 440.18 ;
      RECT 859.82 439.82 860.18 440.18 ;
      RECT 859.11 439.82 859.47 440.18 ;
      RECT 830.53 434.22 830.89 434.58 ;
      RECT 829.82 434.22 830.18 434.58 ;
      RECT 829.11 434.22 829.47 434.58 ;
      RECT 860.53 428.62 860.89 428.98 ;
      RECT 859.82 428.62 860.18 428.98 ;
      RECT 859.11 428.62 859.47 428.98 ;
      RECT 830.53 423.375 830.89 423.735 ;
      RECT 829.82 423.375 830.18 423.735 ;
      RECT 829.11 423.375 829.47 423.735 ;
      RECT 830.53 422.665 830.89 423.025 ;
      RECT 829.82 422.665 830.18 423.025 ;
      RECT 829.11 422.665 829.47 423.025 ;
      RECT 860.53 417.42 860.89 417.78 ;
      RECT 859.82 417.42 860.18 417.78 ;
      RECT 859.11 417.42 859.47 417.78 ;
      RECT 830.53 411.82 830.89 412.18 ;
      RECT 829.82 411.82 830.18 412.18 ;
      RECT 829.11 411.82 829.47 412.18 ;
      RECT 860.53 406.22 860.89 406.58 ;
      RECT 859.82 406.22 860.18 406.58 ;
      RECT 859.11 406.22 859.47 406.58 ;
      RECT 830.53 400.62 830.89 400.98 ;
      RECT 829.82 400.62 830.18 400.98 ;
      RECT 829.11 400.62 829.47 400.98 ;
      RECT 860.53 395.375 860.89 395.735 ;
      RECT 859.82 395.375 860.18 395.735 ;
      RECT 859.11 395.375 859.47 395.735 ;
      RECT 860.53 394.665 860.89 395.025 ;
      RECT 859.82 394.665 860.18 395.025 ;
      RECT 859.11 394.665 859.47 395.025 ;
      RECT 830.53 389.42 830.89 389.78 ;
      RECT 829.82 389.42 830.18 389.78 ;
      RECT 829.11 389.42 829.47 389.78 ;
      RECT 860.53 383.82 860.89 384.18 ;
      RECT 859.82 383.82 860.18 384.18 ;
      RECT 859.11 383.82 859.47 384.18 ;
      RECT 830.53 378.22 830.89 378.58 ;
      RECT 829.82 378.22 830.18 378.58 ;
      RECT 829.11 378.22 829.47 378.58 ;
      RECT 860.53 372.62 860.89 372.98 ;
      RECT 859.82 372.62 860.18 372.98 ;
      RECT 859.11 372.62 859.47 372.98 ;
      RECT 830.53 367.375 830.89 367.735 ;
      RECT 829.82 367.375 830.18 367.735 ;
      RECT 829.11 367.375 829.47 367.735 ;
      RECT 830.53 366.665 830.89 367.025 ;
      RECT 829.82 366.665 830.18 367.025 ;
      RECT 829.11 366.665 829.47 367.025 ;
      RECT 860.53 361.42 860.89 361.78 ;
      RECT 859.82 361.42 860.18 361.78 ;
      RECT 859.11 361.42 859.47 361.78 ;
      RECT 830.53 355.82 830.89 356.18 ;
      RECT 829.82 355.82 830.18 356.18 ;
      RECT 829.11 355.82 829.47 356.18 ;
      RECT 860.53 350.22 860.89 350.58 ;
      RECT 859.82 350.22 860.18 350.58 ;
      RECT 859.11 350.22 859.47 350.58 ;
      RECT 830.53 344.62 830.89 344.98 ;
      RECT 829.82 344.62 830.18 344.98 ;
      RECT 829.11 344.62 829.47 344.98 ;
      RECT 860.53 339.375 860.89 339.735 ;
      RECT 859.82 339.375 860.18 339.735 ;
      RECT 859.11 339.375 859.47 339.735 ;
      RECT 860.53 338.665 860.89 339.025 ;
      RECT 859.82 338.665 860.18 339.025 ;
      RECT 859.11 338.665 859.47 339.025 ;
      RECT 830.53 333.42 830.89 333.78 ;
      RECT 829.82 333.42 830.18 333.78 ;
      RECT 829.11 333.42 829.47 333.78 ;
      RECT 860.53 327.82 860.89 328.18 ;
      RECT 859.82 327.82 860.18 328.18 ;
      RECT 859.11 327.82 859.47 328.18 ;
      RECT 830.53 322.22 830.89 322.58 ;
      RECT 829.82 322.22 830.18 322.58 ;
      RECT 829.11 322.22 829.47 322.58 ;
      RECT 860.53 316.62 860.89 316.98 ;
      RECT 859.82 316.62 860.18 316.98 ;
      RECT 859.11 316.62 859.47 316.98 ;
      RECT 830.53 311.375 830.89 311.735 ;
      RECT 829.82 311.375 830.18 311.735 ;
      RECT 829.11 311.375 829.47 311.735 ;
      RECT 830.53 310.665 830.89 311.025 ;
      RECT 829.82 310.665 830.18 311.025 ;
      RECT 829.11 310.665 829.47 311.025 ;
      RECT 860.53 305.42 860.89 305.78 ;
      RECT 859.82 305.42 860.18 305.78 ;
      RECT 859.11 305.42 859.47 305.78 ;
      RECT 830.53 299.82 830.89 300.18 ;
      RECT 829.82 299.82 830.18 300.18 ;
      RECT 829.11 299.82 829.47 300.18 ;
      RECT 860.53 294.22 860.89 294.58 ;
      RECT 859.82 294.22 860.18 294.58 ;
      RECT 859.11 294.22 859.47 294.58 ;
      RECT 830.53 288.62 830.89 288.98 ;
      RECT 829.82 288.62 830.18 288.98 ;
      RECT 829.11 288.62 829.47 288.98 ;
      RECT 860.53 283.375 860.89 283.735 ;
      RECT 859.82 283.375 860.18 283.735 ;
      RECT 859.11 283.375 859.47 283.735 ;
      RECT 860.53 282.665 860.89 283.025 ;
      RECT 859.82 282.665 860.18 283.025 ;
      RECT 859.11 282.665 859.47 283.025 ;
      RECT 830.53 277.42 830.89 277.78 ;
      RECT 829.82 277.42 830.18 277.78 ;
      RECT 829.11 277.42 829.47 277.78 ;
      RECT 860.53 271.82 860.89 272.18 ;
      RECT 859.82 271.82 860.18 272.18 ;
      RECT 859.11 271.82 859.47 272.18 ;
      RECT 830.53 266.22 830.89 266.58 ;
      RECT 829.82 266.22 830.18 266.58 ;
      RECT 829.11 266.22 829.47 266.58 ;
      RECT 860.53 260.62 860.89 260.98 ;
      RECT 859.82 260.62 860.18 260.98 ;
      RECT 859.11 260.62 859.47 260.98 ;
      RECT 830.53 255.375 830.89 255.735 ;
      RECT 829.82 255.375 830.18 255.735 ;
      RECT 829.11 255.375 829.47 255.735 ;
      RECT 830.53 254.665 830.89 255.025 ;
      RECT 829.82 254.665 830.18 255.025 ;
      RECT 829.11 254.665 829.47 255.025 ;
      RECT 860.53 249.42 860.89 249.78 ;
      RECT 859.82 249.42 860.18 249.78 ;
      RECT 859.11 249.42 859.47 249.78 ;
      RECT 830.53 243.82 830.89 244.18 ;
      RECT 829.82 243.82 830.18 244.18 ;
      RECT 829.11 243.82 829.47 244.18 ;
      RECT 860.53 238.22 860.89 238.58 ;
      RECT 859.82 238.22 860.18 238.58 ;
      RECT 859.11 238.22 859.47 238.58 ;
      RECT 830.53 232.62 830.89 232.98 ;
      RECT 829.82 232.62 830.18 232.98 ;
      RECT 829.11 232.62 829.47 232.98 ;
      RECT 860.53 227.375 860.89 227.735 ;
      RECT 859.82 227.375 860.18 227.735 ;
      RECT 859.11 227.375 859.47 227.735 ;
      RECT 860.53 226.665 860.89 227.025 ;
      RECT 859.82 226.665 860.18 227.025 ;
      RECT 859.11 226.665 859.47 227.025 ;
      RECT 830.53 221.42 830.89 221.78 ;
      RECT 829.82 221.42 830.18 221.78 ;
      RECT 829.11 221.42 829.47 221.78 ;
      RECT 860.53 215.82 860.89 216.18 ;
      RECT 859.82 215.82 860.18 216.18 ;
      RECT 859.11 215.82 859.47 216.18 ;
      RECT 830.53 210.22 830.89 210.58 ;
      RECT 829.82 210.22 830.18 210.58 ;
      RECT 829.11 210.22 829.47 210.58 ;
      RECT 860.53 204.62 860.89 204.98 ;
      RECT 859.82 204.62 860.18 204.98 ;
      RECT 859.11 204.62 859.47 204.98 ;
      RECT 830.53 199.375 830.89 199.735 ;
      RECT 829.82 199.375 830.18 199.735 ;
      RECT 829.11 199.375 829.47 199.735 ;
      RECT 830.53 198.665 830.89 199.025 ;
      RECT 829.82 198.665 830.18 199.025 ;
      RECT 829.11 198.665 829.47 199.025 ;
      RECT 860.53 193.42 860.89 193.78 ;
      RECT 859.82 193.42 860.18 193.78 ;
      RECT 859.11 193.42 859.47 193.78 ;
      RECT 830.53 187.82 830.89 188.18 ;
      RECT 829.82 187.82 830.18 188.18 ;
      RECT 829.11 187.82 829.47 188.18 ;
      RECT 860.53 182.22 860.89 182.58 ;
      RECT 859.82 182.22 860.18 182.58 ;
      RECT 859.11 182.22 859.47 182.58 ;
      RECT 830.53 176.62 830.89 176.98 ;
      RECT 829.82 176.62 830.18 176.98 ;
      RECT 829.11 176.62 829.47 176.98 ;
      RECT 860.53 171.375 860.89 171.735 ;
      RECT 859.82 171.375 860.18 171.735 ;
      RECT 859.11 171.375 859.47 171.735 ;
      RECT 860.53 170.665 860.89 171.025 ;
      RECT 859.82 170.665 860.18 171.025 ;
      RECT 859.11 170.665 859.47 171.025 ;
      RECT 830.53 165.42 830.89 165.78 ;
      RECT 829.82 165.42 830.18 165.78 ;
      RECT 829.11 165.42 829.47 165.78 ;
      RECT 860.53 159.82 860.89 160.18 ;
      RECT 859.82 159.82 860.18 160.18 ;
      RECT 859.11 159.82 859.47 160.18 ;
      RECT 830.53 154.22 830.89 154.58 ;
      RECT 829.82 154.22 830.18 154.58 ;
      RECT 829.11 154.22 829.47 154.58 ;
      RECT 860.53 148.62 860.89 148.98 ;
      RECT 859.82 148.62 860.18 148.98 ;
      RECT 859.11 148.62 859.47 148.98 ;
      RECT 830.53 143.375 830.89 143.735 ;
      RECT 829.82 143.375 830.18 143.735 ;
      RECT 829.11 143.375 829.47 143.735 ;
      RECT 830.53 142.665 830.89 143.025 ;
      RECT 829.82 142.665 830.18 143.025 ;
      RECT 829.11 142.665 829.47 143.025 ;
      RECT 860.53 137.42 860.89 137.78 ;
      RECT 859.82 137.42 860.18 137.78 ;
      RECT 859.11 137.42 859.47 137.78 ;
      RECT 830.53 131.82 830.89 132.18 ;
      RECT 829.82 131.82 830.18 132.18 ;
      RECT 829.11 131.82 829.47 132.18 ;
      RECT 860.53 126.22 860.89 126.58 ;
      RECT 859.82 126.22 860.18 126.58 ;
      RECT 859.11 126.22 859.47 126.58 ;
      RECT 830.53 120.62 830.89 120.98 ;
      RECT 829.82 120.62 830.18 120.98 ;
      RECT 829.11 120.62 829.47 120.98 ;
      RECT 860.53 115.375 860.89 115.735 ;
      RECT 859.82 115.375 860.18 115.735 ;
      RECT 859.11 115.375 859.47 115.735 ;
      RECT 860.53 114.665 860.89 115.025 ;
      RECT 859.82 114.665 860.18 115.025 ;
      RECT 859.11 114.665 859.47 115.025 ;
      RECT 830.53 109.42 830.89 109.78 ;
      RECT 829.82 109.42 830.18 109.78 ;
      RECT 829.11 109.42 829.47 109.78 ;
      RECT 860.53 103.82 860.89 104.18 ;
      RECT 859.82 103.82 860.18 104.18 ;
      RECT 859.11 103.82 859.47 104.18 ;
      RECT 830.53 98.22 830.89 98.58 ;
      RECT 829.82 98.22 830.18 98.58 ;
      RECT 829.11 98.22 829.47 98.58 ;
      RECT 860.53 92.62 860.89 92.98 ;
      RECT 859.82 92.62 860.18 92.98 ;
      RECT 859.11 92.62 859.47 92.98 ;
      RECT 830.53 87.375 830.89 87.735 ;
      RECT 829.82 87.375 830.18 87.735 ;
      RECT 829.11 87.375 829.47 87.735 ;
      RECT 830.53 86.665 830.89 87.025 ;
      RECT 829.82 86.665 830.18 87.025 ;
      RECT 829.11 86.665 829.47 87.025 ;
      RECT 860.53 81.42 860.89 81.78 ;
      RECT 859.82 81.42 860.18 81.78 ;
      RECT 859.11 81.42 859.47 81.78 ;
      RECT 830.53 75.82 830.89 76.18 ;
      RECT 829.82 75.82 830.18 76.18 ;
      RECT 829.11 75.82 829.47 76.18 ;
      RECT 860.53 70.22 860.89 70.58 ;
      RECT 859.82 70.22 860.18 70.58 ;
      RECT 859.11 70.22 859.47 70.58 ;
      RECT 830.53 64.62 830.89 64.98 ;
      RECT 829.82 64.62 830.18 64.98 ;
      RECT 829.11 64.62 829.47 64.98 ;
      RECT 860.53 59.375 860.89 59.735 ;
      RECT 859.82 59.375 860.18 59.735 ;
      RECT 859.11 59.375 859.47 59.735 ;
      RECT 860.53 58.665 860.89 59.025 ;
      RECT 859.82 58.665 860.18 59.025 ;
      RECT 859.11 58.665 859.47 59.025 ;
      RECT 830.53 53.42 830.89 53.78 ;
      RECT 829.82 53.42 830.18 53.78 ;
      RECT 829.11 53.42 829.47 53.78 ;
      RECT 860.53 47.82 860.89 48.18 ;
      RECT 859.82 47.82 860.18 48.18 ;
      RECT 859.11 47.82 859.47 48.18 ;
      RECT 830.53 42.22 830.89 42.58 ;
      RECT 829.82 42.22 830.18 42.58 ;
      RECT 829.11 42.22 829.47 42.58 ;
      RECT 860.53 36.62 860.89 36.98 ;
      RECT 859.82 36.62 860.18 36.98 ;
      RECT 859.11 36.62 859.47 36.98 ;
      RECT 830.53 31.375 830.89 31.735 ;
      RECT 829.82 31.375 830.18 31.735 ;
      RECT 829.11 31.375 829.47 31.735 ;
      RECT 830.53 30.665 830.89 31.025 ;
      RECT 829.82 30.665 830.18 31.025 ;
      RECT 829.11 30.665 829.47 31.025 ;
      RECT 860.53 25.42 860.89 25.78 ;
      RECT 859.82 25.42 860.18 25.78 ;
      RECT 859.11 25.42 859.47 25.78 ;
      RECT 830.53 19.82 830.89 20.18 ;
      RECT 829.82 19.82 830.18 20.18 ;
      RECT 829.11 19.82 829.47 20.18 ;
      RECT 830.53 15.24 830.89 15.6 ;
      RECT 829.82 15.24 830.18 15.6 ;
      RECT 829.11 15.24 829.47 15.6 ;
      RECT 830.53 14.53 830.89 14.89 ;
      RECT 829.82 14.53 830.18 14.89 ;
      RECT 829.11 14.53 829.47 14.89 ;
      RECT 830.53 13.82 830.89 14.18 ;
      RECT 829.82 13.82 830.18 14.18 ;
      RECT 829.11 13.82 829.47 14.18 ;
      RECT 830.53 13.11 830.89 13.47 ;
      RECT 829.82 13.11 830.18 13.47 ;
      RECT 829.11 13.11 829.47 13.47 ;
      RECT 830.53 12.4 830.89 12.76 ;
      RECT 829.82 12.4 830.18 12.76 ;
      RECT 829.11 12.4 829.47 12.76 ;
      RECT 860.53 9.24 860.89 9.6 ;
      RECT 859.82 9.24 860.18 9.6 ;
      RECT 859.11 9.24 859.47 9.6 ;
      RECT 860.53 8.53 860.89 8.89 ;
      RECT 859.82 8.53 860.18 8.89 ;
      RECT 859.11 8.53 859.47 8.89 ;
      RECT 860.53 7.82 860.89 8.18 ;
      RECT 859.82 7.82 860.18 8.18 ;
      RECT 859.11 7.82 859.47 8.18 ;
      RECT 860.53 7.11 860.89 7.47 ;
      RECT 859.82 7.11 860.18 7.47 ;
      RECT 859.11 7.11 859.47 7.47 ;
      RECT 860.53 6.4 860.89 6.76 ;
      RECT 859.82 6.4 860.18 6.76 ;
      RECT 859.11 6.4 859.47 6.76 ;
    LAYER OVERLAP ;
      POLYGON 0 0 0 885.6 885.6 885.6 885.6 0 ;
  END
  PROPERTY expanded_util 0.73 ;
END unpu_top

END LIBRARY
